VERSION 5.8 ;
BUSBITCHARS "[]" ;
DIVIDERCHAR "/" ;
UNITS
    DATABASE MICRONS 1000 ;
END UNITS

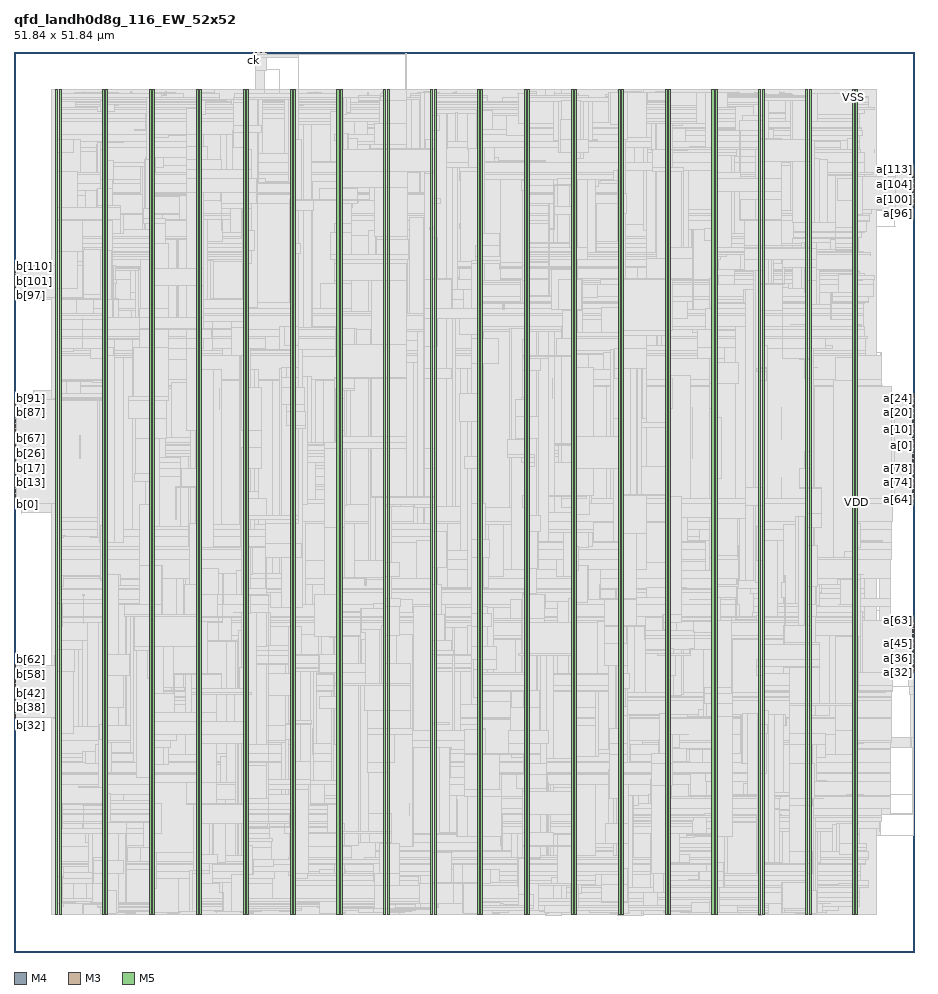
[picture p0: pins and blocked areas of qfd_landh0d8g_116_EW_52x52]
MACRO qfd_landh0d8g_116_EW_52x52
  FOREIGN qfd_landh0d8g_116_EW_52x52 0 0 ;
  CLASS BLOCK ;
  SIZE 51.84 BY 51.84 ;
  PIN a[0]
    DIRECTION INPUT ;
    USE SIGNAL ;
    PORT
      LAYER M4 ;
        RECT  51.756 29.136 51.84 29.16 ;
    END
  END a[0]
  PIN a[100]
    DIRECTION INPUT ;
    USE SIGNAL ;
    PORT
      LAYER M4 ;
        RECT  51.756 43.344 51.84 43.368 ;
    END
  END a[100]
  PIN a[101]
    DIRECTION INPUT ;
    USE SIGNAL ;
    PORT
      LAYER M4 ;
        RECT  51.756 43.44 51.84 43.464 ;
    END
  END a[101]
  PIN a[102]
    DIRECTION INPUT ;
    USE SIGNAL ;
    PORT
      LAYER M4 ;
        RECT  51.756 43.536 51.84 43.56 ;
    END
  END a[102]
  PIN a[103]
    DIRECTION INPUT ;
    USE SIGNAL ;
    PORT
      LAYER M4 ;
        RECT  51.756 43.632 51.84 43.656 ;
    END
  END a[103]
  PIN a[104]
    DIRECTION INPUT ;
    USE SIGNAL ;
    PORT
      LAYER M4 ;
        RECT  51.756 43.728 51.84 43.752 ;
    END
  END a[104]
  PIN a[105]
    DIRECTION INPUT ;
    USE SIGNAL ;
    PORT
      LAYER M4 ;
        RECT  51.756 43.824 51.84 43.848 ;
    END
  END a[105]
  PIN a[106]
    DIRECTION INPUT ;
    USE SIGNAL ;
    PORT
      LAYER M4 ;
        RECT  51.756 43.92 51.84 43.944 ;
    END
  END a[106]
  PIN a[107]
    DIRECTION INPUT ;
    USE SIGNAL ;
    PORT
      LAYER M4 ;
        RECT  51.756 44.016 51.84 44.04 ;
    END
  END a[107]
  PIN a[108]
    DIRECTION INPUT ;
    USE SIGNAL ;
    PORT
      LAYER M4 ;
        RECT  51.756 44.112 51.84 44.136 ;
    END
  END a[108]
  PIN a[109]
    DIRECTION INPUT ;
    USE SIGNAL ;
    PORT
      LAYER M4 ;
        RECT  51.756 44.208 51.84 44.232 ;
    END
  END a[109]
  PIN a[10]
    DIRECTION INPUT ;
    USE SIGNAL ;
    PORT
      LAYER M4 ;
        RECT  51.756 30.096 51.84 30.12 ;
    END
  END a[10]
  PIN a[110]
    DIRECTION INPUT ;
    USE SIGNAL ;
    PORT
      LAYER M4 ;
        RECT  51.756 44.304 51.84 44.328 ;
    END
  END a[110]
  PIN a[111]
    DIRECTION INPUT ;
    USE SIGNAL ;
    PORT
      LAYER M4 ;
        RECT  51.756 44.4 51.84 44.424 ;
    END
  END a[111]
  PIN a[112]
    DIRECTION INPUT ;
    USE SIGNAL ;
    PORT
      LAYER M4 ;
        RECT  51.756 44.496 51.84 44.52 ;
    END
  END a[112]
  PIN a[113]
    DIRECTION INPUT ;
    USE SIGNAL ;
    PORT
      LAYER M4 ;
        RECT  51.756 44.592 51.84 44.616 ;
    END
  END a[113]
  PIN a[114]
    DIRECTION INPUT ;
    USE SIGNAL ;
    PORT
      LAYER M4 ;
        RECT  51.756 44.688 51.84 44.712 ;
    END
  END a[114]
  PIN a[115]
    DIRECTION INPUT ;
    USE SIGNAL ;
    PORT
      LAYER M4 ;
        RECT  51.756 44.784 51.84 44.808 ;
    END
  END a[115]
  PIN a[11]
    DIRECTION INPUT ;
    USE SIGNAL ;
    PORT
      LAYER M4 ;
        RECT  51.756 30.192 51.84 30.216 ;
    END
  END a[11]
  PIN a[12]
    DIRECTION INPUT ;
    USE SIGNAL ;
    PORT
      LAYER M4 ;
        RECT  51.756 30.288 51.84 30.312 ;
    END
  END a[12]
  PIN a[13]
    DIRECTION INPUT ;
    USE SIGNAL ;
    PORT
      LAYER M4 ;
        RECT  51.756 30.384 51.84 30.408 ;
    END
  END a[13]
  PIN a[14]
    DIRECTION INPUT ;
    USE SIGNAL ;
    PORT
      LAYER M4 ;
        RECT  51.756 30.48 51.84 30.504 ;
    END
  END a[14]
  PIN a[15]
    DIRECTION INPUT ;
    USE SIGNAL ;
    PORT
      LAYER M4 ;
        RECT  51.756 30.576 51.84 30.6 ;
    END
  END a[15]
  PIN a[16]
    DIRECTION INPUT ;
    USE SIGNAL ;
    PORT
      LAYER M4 ;
        RECT  51.756 30.672 51.84 30.696 ;
    END
  END a[16]
  PIN a[17]
    DIRECTION INPUT ;
    USE SIGNAL ;
    PORT
      LAYER M4 ;
        RECT  51.756 30.768 51.84 30.792 ;
    END
  END a[17]
  PIN a[18]
    DIRECTION INPUT ;
    USE SIGNAL ;
    PORT
      LAYER M4 ;
        RECT  51.756 30.864 51.84 30.888 ;
    END
  END a[18]
  PIN a[19]
    DIRECTION INPUT ;
    USE SIGNAL ;
    PORT
      LAYER M4 ;
        RECT  51.756 30.96 51.84 30.984 ;
    END
  END a[19]
  PIN a[1]
    DIRECTION INPUT ;
    USE SIGNAL ;
    PORT
      LAYER M4 ;
        RECT  51.756 29.232 51.84 29.256 ;
    END
  END a[1]
  PIN a[20]
    DIRECTION INPUT ;
    USE SIGNAL ;
    PORT
      LAYER M4 ;
        RECT  51.756 31.056 51.84 31.08 ;
    END
  END a[20]
  PIN a[21]
    DIRECTION INPUT ;
    USE SIGNAL ;
    PORT
      LAYER M4 ;
        RECT  51.756 31.152 51.84 31.176 ;
    END
  END a[21]
  PIN a[22]
    DIRECTION INPUT ;
    USE SIGNAL ;
    PORT
      LAYER M4 ;
        RECT  51.756 31.248 51.84 31.272 ;
    END
  END a[22]
  PIN a[23]
    DIRECTION INPUT ;
    USE SIGNAL ;
    PORT
      LAYER M4 ;
        RECT  51.756 31.344 51.84 31.368 ;
    END
  END a[23]
  PIN a[24]
    DIRECTION INPUT ;
    USE SIGNAL ;
    PORT
      LAYER M4 ;
        RECT  51.756 31.44 51.84 31.464 ;
    END
  END a[24]
  PIN a[25]
    DIRECTION INPUT ;
    USE SIGNAL ;
    PORT
      LAYER M4 ;
        RECT  51.756 31.536 51.84 31.56 ;
    END
  END a[25]
  PIN a[26]
    DIRECTION INPUT ;
    USE SIGNAL ;
    PORT
      LAYER M4 ;
        RECT  51.756 31.632 51.84 31.656 ;
    END
  END a[26]
  PIN a[27]
    DIRECTION INPUT ;
    USE SIGNAL ;
    PORT
      LAYER M4 ;
        RECT  51.756 31.728 51.84 31.752 ;
    END
  END a[27]
  PIN a[28]
    DIRECTION INPUT ;
    USE SIGNAL ;
    PORT
      LAYER M4 ;
        RECT  51.756 31.824 51.84 31.848 ;
    END
  END a[28]
  PIN a[29]
    DIRECTION INPUT ;
    USE SIGNAL ;
    PORT
      LAYER M4 ;
        RECT  51.756 31.92 51.84 31.944 ;
    END
  END a[29]
  PIN a[2]
    DIRECTION INPUT ;
    USE SIGNAL ;
    PORT
      LAYER M4 ;
        RECT  51.756 29.328 51.84 29.352 ;
    END
  END a[2]
  PIN a[30]
    DIRECTION INPUT ;
    USE SIGNAL ;
    PORT
      LAYER M4 ;
        RECT  51.756 32.016 51.84 32.04 ;
    END
  END a[30]
  PIN a[31]
    DIRECTION INPUT ;
    USE SIGNAL ;
    PORT
      LAYER M4 ;
        RECT  51.756 32.112 51.84 32.136 ;
    END
  END a[31]
  PIN a[32]
    DIRECTION INPUT ;
    USE SIGNAL ;
    PORT
      LAYER M4 ;
        RECT  51.756 16.08 51.84 16.104 ;
    END
  END a[32]
  PIN a[33]
    DIRECTION INPUT ;
    USE SIGNAL ;
    PORT
      LAYER M4 ;
        RECT  51.756 16.176 51.84 16.2 ;
    END
  END a[33]
  PIN a[34]
    DIRECTION INPUT ;
    USE SIGNAL ;
    PORT
      LAYER M4 ;
        RECT  51.756 16.272 51.84 16.296 ;
    END
  END a[34]
  PIN a[35]
    DIRECTION INPUT ;
    USE SIGNAL ;
    PORT
      LAYER M4 ;
        RECT  51.756 16.368 51.84 16.392 ;
    END
  END a[35]
  PIN a[36]
    DIRECTION INPUT ;
    USE SIGNAL ;
    PORT
      LAYER M4 ;
        RECT  51.756 16.464 51.84 16.488 ;
    END
  END a[36]
  PIN a[37]
    DIRECTION INPUT ;
    USE SIGNAL ;
    PORT
      LAYER M4 ;
        RECT  51.756 16.56 51.84 16.584 ;
    END
  END a[37]
  PIN a[38]
    DIRECTION INPUT ;
    USE SIGNAL ;
    PORT
      LAYER M4 ;
        RECT  51.756 16.656 51.84 16.68 ;
    END
  END a[38]
  PIN a[39]
    DIRECTION INPUT ;
    USE SIGNAL ;
    PORT
      LAYER M4 ;
        RECT  51.756 16.752 51.84 16.776 ;
    END
  END a[39]
  PIN a[3]
    DIRECTION INPUT ;
    USE SIGNAL ;
    PORT
      LAYER M4 ;
        RECT  51.756 29.424 51.84 29.448 ;
    END
  END a[3]
  PIN a[40]
    DIRECTION INPUT ;
    USE SIGNAL ;
    PORT
      LAYER M4 ;
        RECT  51.756 16.848 51.84 16.872 ;
    END
  END a[40]
  PIN a[41]
    DIRECTION INPUT ;
    USE SIGNAL ;
    PORT
      LAYER M4 ;
        RECT  51.756 16.944 51.84 16.968 ;
    END
  END a[41]
  PIN a[42]
    DIRECTION INPUT ;
    USE SIGNAL ;
    PORT
      LAYER M4 ;
        RECT  51.756 17.04 51.84 17.064 ;
    END
  END a[42]
  PIN a[43]
    DIRECTION INPUT ;
    USE SIGNAL ;
    PORT
      LAYER M4 ;
        RECT  51.756 17.136 51.84 17.16 ;
    END
  END a[43]
  PIN a[44]
    DIRECTION INPUT ;
    USE SIGNAL ;
    PORT
      LAYER M4 ;
        RECT  51.756 17.232 51.84 17.256 ;
    END
  END a[44]
  PIN a[45]
    DIRECTION INPUT ;
    USE SIGNAL ;
    PORT
      LAYER M4 ;
        RECT  51.756 17.328 51.84 17.352 ;
    END
  END a[45]
  PIN a[46]
    DIRECTION INPUT ;
    USE SIGNAL ;
    PORT
      LAYER M4 ;
        RECT  51.756 17.424 51.84 17.448 ;
    END
  END a[46]
  PIN a[47]
    DIRECTION INPUT ;
    USE SIGNAL ;
    PORT
      LAYER M4 ;
        RECT  51.756 17.52 51.84 17.544 ;
    END
  END a[47]
  PIN a[48]
    DIRECTION INPUT ;
    USE SIGNAL ;
    PORT
      LAYER M4 ;
        RECT  51.756 17.616 51.84 17.64 ;
    END
  END a[48]
  PIN a[49]
    DIRECTION INPUT ;
    USE SIGNAL ;
    PORT
      LAYER M4 ;
        RECT  51.756 17.712 51.84 17.736 ;
    END
  END a[49]
  PIN a[4]
    DIRECTION INPUT ;
    USE SIGNAL ;
    PORT
      LAYER M4 ;
        RECT  51.756 29.52 51.84 29.544 ;
    END
  END a[4]
  PIN a[50]
    DIRECTION INPUT ;
    USE SIGNAL ;
    PORT
      LAYER M4 ;
        RECT  51.756 17.808 51.84 17.832 ;
    END
  END a[50]
  PIN a[51]
    DIRECTION INPUT ;
    USE SIGNAL ;
    PORT
      LAYER M4 ;
        RECT  51.756 17.904 51.84 17.928 ;
    END
  END a[51]
  PIN a[52]
    DIRECTION INPUT ;
    USE SIGNAL ;
    PORT
      LAYER M4 ;
        RECT  51.756 18 51.84 18.024 ;
    END
  END a[52]
  PIN a[53]
    DIRECTION INPUT ;
    USE SIGNAL ;
    PORT
      LAYER M4 ;
        RECT  51.756 18.096 51.84 18.12 ;
    END
  END a[53]
  PIN a[54]
    DIRECTION INPUT ;
    USE SIGNAL ;
    PORT
      LAYER M4 ;
        RECT  51.756 18.192 51.84 18.216 ;
    END
  END a[54]
  PIN a[55]
    DIRECTION INPUT ;
    USE SIGNAL ;
    PORT
      LAYER M4 ;
        RECT  51.756 18.288 51.84 18.312 ;
    END
  END a[55]
  PIN a[56]
    DIRECTION INPUT ;
    USE SIGNAL ;
    PORT
      LAYER M4 ;
        RECT  51.756 18.384 51.84 18.408 ;
    END
  END a[56]
  PIN a[57]
    DIRECTION INPUT ;
    USE SIGNAL ;
    PORT
      LAYER M4 ;
        RECT  51.756 18.48 51.84 18.504 ;
    END
  END a[57]
  PIN a[58]
    DIRECTION INPUT ;
    USE SIGNAL ;
    PORT
      LAYER M4 ;
        RECT  51.756 18.576 51.84 18.6 ;
    END
  END a[58]
  PIN a[59]
    DIRECTION INPUT ;
    USE SIGNAL ;
    PORT
      LAYER M4 ;
        RECT  51.756 18.672 51.84 18.696 ;
    END
  END a[59]
  PIN a[5]
    DIRECTION INPUT ;
    USE SIGNAL ;
    PORT
      LAYER M4 ;
        RECT  51.756 29.616 51.84 29.64 ;
    END
  END a[5]
  PIN a[60]
    DIRECTION INPUT ;
    USE SIGNAL ;
    PORT
      LAYER M4 ;
        RECT  51.756 18.768 51.84 18.792 ;
    END
  END a[60]
  PIN a[61]
    DIRECTION INPUT ;
    USE SIGNAL ;
    PORT
      LAYER M4 ;
        RECT  51.756 18.864 51.84 18.888 ;
    END
  END a[61]
  PIN a[62]
    DIRECTION INPUT ;
    USE SIGNAL ;
    PORT
      LAYER M4 ;
        RECT  51.756 18.96 51.84 18.984 ;
    END
  END a[62]
  PIN a[63]
    DIRECTION INPUT ;
    USE SIGNAL ;
    PORT
      LAYER M4 ;
        RECT  51.756 19.056 51.84 19.08 ;
    END
  END a[63]
  PIN a[64]
    DIRECTION INPUT ;
    USE SIGNAL ;
    PORT
      LAYER M4 ;
        RECT  51.756 26.064 51.84 26.088 ;
    END
  END a[64]
  PIN a[65]
    DIRECTION INPUT ;
    USE SIGNAL ;
    PORT
      LAYER M4 ;
        RECT  51.756 26.16 51.84 26.184 ;
    END
  END a[65]
  PIN a[66]
    DIRECTION INPUT ;
    USE SIGNAL ;
    PORT
      LAYER M4 ;
        RECT  51.756 26.256 51.84 26.28 ;
    END
  END a[66]
  PIN a[67]
    DIRECTION INPUT ;
    USE SIGNAL ;
    PORT
      LAYER M4 ;
        RECT  51.756 26.352 51.84 26.376 ;
    END
  END a[67]
  PIN a[68]
    DIRECTION INPUT ;
    USE SIGNAL ;
    PORT
      LAYER M4 ;
        RECT  51.756 26.448 51.84 26.472 ;
    END
  END a[68]
  PIN a[69]
    DIRECTION INPUT ;
    USE SIGNAL ;
    PORT
      LAYER M4 ;
        RECT  51.756 26.544 51.84 26.568 ;
    END
  END a[69]
  PIN a[6]
    DIRECTION INPUT ;
    USE SIGNAL ;
    PORT
      LAYER M4 ;
        RECT  51.756 29.712 51.84 29.736 ;
    END
  END a[6]
  PIN a[70]
    DIRECTION INPUT ;
    USE SIGNAL ;
    PORT
      LAYER M4 ;
        RECT  51.756 26.64 51.84 26.664 ;
    END
  END a[70]
  PIN a[71]
    DIRECTION INPUT ;
    USE SIGNAL ;
    PORT
      LAYER M4 ;
        RECT  51.756 26.736 51.84 26.76 ;
    END
  END a[71]
  PIN a[72]
    DIRECTION INPUT ;
    USE SIGNAL ;
    PORT
      LAYER M4 ;
        RECT  51.756 26.832 51.84 26.856 ;
    END
  END a[72]
  PIN a[73]
    DIRECTION INPUT ;
    USE SIGNAL ;
    PORT
      LAYER M4 ;
        RECT  51.756 26.928 51.84 26.952 ;
    END
  END a[73]
  PIN a[74]
    DIRECTION INPUT ;
    USE SIGNAL ;
    PORT
      LAYER M4 ;
        RECT  51.756 27.024 51.84 27.048 ;
    END
  END a[74]
  PIN a[75]
    DIRECTION INPUT ;
    USE SIGNAL ;
    PORT
      LAYER M4 ;
        RECT  51.756 27.12 51.84 27.144 ;
    END
  END a[75]
  PIN a[76]
    DIRECTION INPUT ;
    USE SIGNAL ;
    PORT
      LAYER M4 ;
        RECT  51.756 27.216 51.84 27.24 ;
    END
  END a[76]
  PIN a[77]
    DIRECTION INPUT ;
    USE SIGNAL ;
    PORT
      LAYER M4 ;
        RECT  51.756 27.312 51.84 27.336 ;
    END
  END a[77]
  PIN a[78]
    DIRECTION INPUT ;
    USE SIGNAL ;
    PORT
      LAYER M4 ;
        RECT  51.756 27.408 51.84 27.432 ;
    END
  END a[78]
  PIN a[79]
    DIRECTION INPUT ;
    USE SIGNAL ;
    PORT
      LAYER M4 ;
        RECT  51.756 27.504 51.84 27.528 ;
    END
  END a[79]
  PIN a[7]
    DIRECTION INPUT ;
    USE SIGNAL ;
    PORT
      LAYER M4 ;
        RECT  51.756 29.808 51.84 29.832 ;
    END
  END a[7]
  PIN a[80]
    DIRECTION INPUT ;
    USE SIGNAL ;
    PORT
      LAYER M4 ;
        RECT  51.756 27.6 51.84 27.624 ;
    END
  END a[80]
  PIN a[81]
    DIRECTION INPUT ;
    USE SIGNAL ;
    PORT
      LAYER M4 ;
        RECT  51.756 27.696 51.84 27.72 ;
    END
  END a[81]
  PIN a[82]
    DIRECTION INPUT ;
    USE SIGNAL ;
    PORT
      LAYER M4 ;
        RECT  51.756 27.792 51.84 27.816 ;
    END
  END a[82]
  PIN a[83]
    DIRECTION INPUT ;
    USE SIGNAL ;
    PORT
      LAYER M4 ;
        RECT  51.756 27.888 51.84 27.912 ;
    END
  END a[83]
  PIN a[84]
    DIRECTION INPUT ;
    USE SIGNAL ;
    PORT
      LAYER M4 ;
        RECT  51.756 27.984 51.84 28.008 ;
    END
  END a[84]
  PIN a[85]
    DIRECTION INPUT ;
    USE SIGNAL ;
    PORT
      LAYER M4 ;
        RECT  51.756 28.08 51.84 28.104 ;
    END
  END a[85]
  PIN a[86]
    DIRECTION INPUT ;
    USE SIGNAL ;
    PORT
      LAYER M4 ;
        RECT  51.756 28.176 51.84 28.2 ;
    END
  END a[86]
  PIN a[87]
    DIRECTION INPUT ;
    USE SIGNAL ;
    PORT
      LAYER M4 ;
        RECT  51.756 28.272 51.84 28.296 ;
    END
  END a[87]
  PIN a[88]
    DIRECTION INPUT ;
    USE SIGNAL ;
    PORT
      LAYER M4 ;
        RECT  51.756 28.368 51.84 28.392 ;
    END
  END a[88]
  PIN a[89]
    DIRECTION INPUT ;
    USE SIGNAL ;
    PORT
      LAYER M4 ;
        RECT  51.756 28.464 51.84 28.488 ;
    END
  END a[89]
  PIN a[8]
    DIRECTION INPUT ;
    USE SIGNAL ;
    PORT
      LAYER M4 ;
        RECT  51.756 29.904 51.84 29.928 ;
    END
  END a[8]
  PIN a[90]
    DIRECTION INPUT ;
    USE SIGNAL ;
    PORT
      LAYER M4 ;
        RECT  51.756 28.56 51.84 28.584 ;
    END
  END a[90]
  PIN a[91]
    DIRECTION INPUT ;
    USE SIGNAL ;
    PORT
      LAYER M4 ;
        RECT  51.756 28.656 51.84 28.68 ;
    END
  END a[91]
  PIN a[92]
    DIRECTION INPUT ;
    USE SIGNAL ;
    PORT
      LAYER M4 ;
        RECT  51.756 28.752 51.84 28.776 ;
    END
  END a[92]
  PIN a[93]
    DIRECTION INPUT ;
    USE SIGNAL ;
    PORT
      LAYER M4 ;
        RECT  51.756 28.848 51.84 28.872 ;
    END
  END a[93]
  PIN a[94]
    DIRECTION INPUT ;
    USE SIGNAL ;
    PORT
      LAYER M4 ;
        RECT  51.756 28.944 51.84 28.968 ;
    END
  END a[94]
  PIN a[95]
    DIRECTION INPUT ;
    USE SIGNAL ;
    PORT
      LAYER M4 ;
        RECT  51.756 29.04 51.84 29.064 ;
    END
  END a[95]
  PIN a[96]
    DIRECTION INPUT ;
    USE SIGNAL ;
    PORT
      LAYER M4 ;
        RECT  51.756 42.96 51.84 42.984 ;
    END
  END a[96]
  PIN a[97]
    DIRECTION INPUT ;
    USE SIGNAL ;
    PORT
      LAYER M4 ;
        RECT  51.756 43.056 51.84 43.08 ;
    END
  END a[97]
  PIN a[98]
    DIRECTION INPUT ;
    USE SIGNAL ;
    PORT
      LAYER M4 ;
        RECT  51.756 43.152 51.84 43.176 ;
    END
  END a[98]
  PIN a[99]
    DIRECTION INPUT ;
    USE SIGNAL ;
    PORT
      LAYER M4 ;
        RECT  51.756 43.248 51.84 43.272 ;
    END
  END a[99]
  PIN a[9]
    DIRECTION INPUT ;
    USE SIGNAL ;
    PORT
      LAYER M4 ;
        RECT  51.756 30 51.84 30.024 ;
    END
  END a[9]
  PIN b[0]
    DIRECTION OUTPUT ;
    USE SIGNAL ;
    PORT
      LAYER M4 ;
        RECT  0 25.776 0.084 25.8 ;
    END
  END b[0]
  PIN b[100]
    DIRECTION OUTPUT ;
    USE SIGNAL ;
    PORT
      LAYER M4 ;
        RECT  0 38.064 0.084 38.088 ;
    END
  END b[100]
  PIN b[101]
    DIRECTION OUTPUT ;
    USE SIGNAL ;
    PORT
      LAYER M4 ;
        RECT  0 38.16 0.084 38.184 ;
    END
  END b[101]
  PIN b[102]
    DIRECTION OUTPUT ;
    USE SIGNAL ;
    PORT
      LAYER M4 ;
        RECT  0 38.256 0.084 38.28 ;
    END
  END b[102]
  PIN b[103]
    DIRECTION OUTPUT ;
    USE SIGNAL ;
    PORT
      LAYER M4 ;
        RECT  0 38.352 0.084 38.376 ;
    END
  END b[103]
  PIN b[104]
    DIRECTION OUTPUT ;
    USE SIGNAL ;
    PORT
      LAYER M4 ;
        RECT  0 38.448 0.084 38.472 ;
    END
  END b[104]
  PIN b[105]
    DIRECTION OUTPUT ;
    USE SIGNAL ;
    PORT
      LAYER M4 ;
        RECT  0 38.544 0.084 38.568 ;
    END
  END b[105]
  PIN b[106]
    DIRECTION OUTPUT ;
    USE SIGNAL ;
    PORT
      LAYER M4 ;
        RECT  0 38.64 0.084 38.664 ;
    END
  END b[106]
  PIN b[107]
    DIRECTION OUTPUT ;
    USE SIGNAL ;
    PORT
      LAYER M4 ;
        RECT  0 38.736 0.084 38.76 ;
    END
  END b[107]
  PIN b[108]
    DIRECTION OUTPUT ;
    USE SIGNAL ;
    PORT
      LAYER M4 ;
        RECT  0 38.832 0.084 38.856 ;
    END
  END b[108]
  PIN b[109]
    DIRECTION OUTPUT ;
    USE SIGNAL ;
    PORT
      LAYER M4 ;
        RECT  0 38.928 0.084 38.952 ;
    END
  END b[109]
  PIN b[10]
    DIRECTION OUTPUT ;
    USE SIGNAL ;
    PORT
      LAYER M4 ;
        RECT  0 26.736 0.084 26.76 ;
    END
  END b[10]
  PIN b[110]
    DIRECTION OUTPUT ;
    USE SIGNAL ;
    PORT
      LAYER M4 ;
        RECT  0 39.024 0.084 39.048 ;
    END
  END b[110]
  PIN b[111]
    DIRECTION OUTPUT ;
    USE SIGNAL ;
    PORT
      LAYER M4 ;
        RECT  0 39.12 0.084 39.144 ;
    END
  END b[111]
  PIN b[112]
    DIRECTION OUTPUT ;
    USE SIGNAL ;
    PORT
      LAYER M4 ;
        RECT  0 39.216 0.084 39.24 ;
    END
  END b[112]
  PIN b[113]
    DIRECTION OUTPUT ;
    USE SIGNAL ;
    PORT
      LAYER M4 ;
        RECT  0 39.312 0.084 39.336 ;
    END
  END b[113]
  PIN b[114]
    DIRECTION OUTPUT ;
    USE SIGNAL ;
    PORT
      LAYER M4 ;
        RECT  0 39.408 0.084 39.432 ;
    END
  END b[114]
  PIN b[115]
    DIRECTION OUTPUT ;
    USE SIGNAL ;
    PORT
      LAYER M4 ;
        RECT  0 39.504 0.084 39.528 ;
    END
  END b[115]
  PIN b[11]
    DIRECTION OUTPUT ;
    USE SIGNAL ;
    PORT
      LAYER M4 ;
        RECT  0 26.832 0.084 26.856 ;
    END
  END b[11]
  PIN b[12]
    DIRECTION OUTPUT ;
    USE SIGNAL ;
    PORT
      LAYER M4 ;
        RECT  0 26.928 0.084 26.952 ;
    END
  END b[12]
  PIN b[13]
    DIRECTION OUTPUT ;
    USE SIGNAL ;
    PORT
      LAYER M4 ;
        RECT  0 27.024 0.084 27.048 ;
    END
  END b[13]
  PIN b[14]
    DIRECTION OUTPUT ;
    USE SIGNAL ;
    PORT
      LAYER M4 ;
        RECT  0 27.12 0.084 27.144 ;
    END
  END b[14]
  PIN b[15]
    DIRECTION OUTPUT ;
    USE SIGNAL ;
    PORT
      LAYER M4 ;
        RECT  0 27.216 0.084 27.24 ;
    END
  END b[15]
  PIN b[16]
    DIRECTION OUTPUT ;
    USE SIGNAL ;
    PORT
      LAYER M4 ;
        RECT  0 27.312 0.084 27.336 ;
    END
  END b[16]
  PIN b[17]
    DIRECTION OUTPUT ;
    USE SIGNAL ;
    PORT
      LAYER M4 ;
        RECT  0 27.408 0.084 27.432 ;
    END
  END b[17]
  PIN b[18]
    DIRECTION OUTPUT ;
    USE SIGNAL ;
    PORT
      LAYER M4 ;
        RECT  0 27.504 0.084 27.528 ;
    END
  END b[18]
  PIN b[19]
    DIRECTION OUTPUT ;
    USE SIGNAL ;
    PORT
      LAYER M4 ;
        RECT  0 27.6 0.084 27.624 ;
    END
  END b[19]
  PIN b[1]
    DIRECTION OUTPUT ;
    USE SIGNAL ;
    PORT
      LAYER M4 ;
        RECT  0 25.872 0.084 25.896 ;
    END
  END b[1]
  PIN b[20]
    DIRECTION OUTPUT ;
    USE SIGNAL ;
    PORT
      LAYER M4 ;
        RECT  0 27.696 0.084 27.72 ;
    END
  END b[20]
  PIN b[21]
    DIRECTION OUTPUT ;
    USE SIGNAL ;
    PORT
      LAYER M4 ;
        RECT  0 27.792 0.084 27.816 ;
    END
  END b[21]
  PIN b[22]
    DIRECTION OUTPUT ;
    USE SIGNAL ;
    PORT
      LAYER M4 ;
        RECT  0 27.888 0.084 27.912 ;
    END
  END b[22]
  PIN b[23]
    DIRECTION OUTPUT ;
    USE SIGNAL ;
    PORT
      LAYER M4 ;
        RECT  0 27.984 0.084 28.008 ;
    END
  END b[23]
  PIN b[24]
    DIRECTION OUTPUT ;
    USE SIGNAL ;
    PORT
      LAYER M4 ;
        RECT  0 28.08 0.084 28.104 ;
    END
  END b[24]
  PIN b[25]
    DIRECTION OUTPUT ;
    USE SIGNAL ;
    PORT
      LAYER M4 ;
        RECT  0 28.176 0.084 28.2 ;
    END
  END b[25]
  PIN b[26]
    DIRECTION OUTPUT ;
    USE SIGNAL ;
    PORT
      LAYER M4 ;
        RECT  0 28.272 0.084 28.296 ;
    END
  END b[26]
  PIN b[27]
    DIRECTION OUTPUT ;
    USE SIGNAL ;
    PORT
      LAYER M4 ;
        RECT  0 28.368 0.084 28.392 ;
    END
  END b[27]
  PIN b[28]
    DIRECTION OUTPUT ;
    USE SIGNAL ;
    PORT
      LAYER M4 ;
        RECT  0 28.464 0.084 28.488 ;
    END
  END b[28]
  PIN b[29]
    DIRECTION OUTPUT ;
    USE SIGNAL ;
    PORT
      LAYER M4 ;
        RECT  0 28.56 0.084 28.584 ;
    END
  END b[29]
  PIN b[2]
    DIRECTION OUTPUT ;
    USE SIGNAL ;
    PORT
      LAYER M4 ;
        RECT  0 25.968 0.084 25.992 ;
    END
  END b[2]
  PIN b[30]
    DIRECTION OUTPUT ;
    USE SIGNAL ;
    PORT
      LAYER M4 ;
        RECT  0 28.656 0.084 28.68 ;
    END
  END b[30]
  PIN b[31]
    DIRECTION OUTPUT ;
    USE SIGNAL ;
    PORT
      LAYER M4 ;
        RECT  0 28.752 0.084 28.776 ;
    END
  END b[31]
  PIN b[32]
    DIRECTION OUTPUT ;
    USE SIGNAL ;
    PORT
      LAYER M4 ;
        RECT  0 13.488 0.084 13.512 ;
    END
  END b[32]
  PIN b[33]
    DIRECTION OUTPUT ;
    USE SIGNAL ;
    PORT
      LAYER M4 ;
        RECT  0 13.584 0.084 13.608 ;
    END
  END b[33]
  PIN b[34]
    DIRECTION OUTPUT ;
    USE SIGNAL ;
    PORT
      LAYER M4 ;
        RECT  0 13.68 0.084 13.704 ;
    END
  END b[34]
  PIN b[35]
    DIRECTION OUTPUT ;
    USE SIGNAL ;
    PORT
      LAYER M4 ;
        RECT  0 13.776 0.084 13.8 ;
    END
  END b[35]
  PIN b[36]
    DIRECTION OUTPUT ;
    USE SIGNAL ;
    PORT
      LAYER M4 ;
        RECT  0 13.872 0.084 13.896 ;
    END
  END b[36]
  PIN b[37]
    DIRECTION OUTPUT ;
    USE SIGNAL ;
    PORT
      LAYER M4 ;
        RECT  0 13.968 0.084 13.992 ;
    END
  END b[37]
  PIN b[38]
    DIRECTION OUTPUT ;
    USE SIGNAL ;
    PORT
      LAYER M4 ;
        RECT  0 14.064 0.084 14.088 ;
    END
  END b[38]
  PIN b[39]
    DIRECTION OUTPUT ;
    USE SIGNAL ;
    PORT
      LAYER M4 ;
        RECT  0 14.16 0.084 14.184 ;
    END
  END b[39]
  PIN b[3]
    DIRECTION OUTPUT ;
    USE SIGNAL ;
    PORT
      LAYER M4 ;
        RECT  0 26.064 0.084 26.088 ;
    END
  END b[3]
  PIN b[40]
    DIRECTION OUTPUT ;
    USE SIGNAL ;
    PORT
      LAYER M4 ;
        RECT  0 14.256 0.084 14.28 ;
    END
  END b[40]
  PIN b[41]
    DIRECTION OUTPUT ;
    USE SIGNAL ;
    PORT
      LAYER M4 ;
        RECT  0 14.352 0.084 14.376 ;
    END
  END b[41]
  PIN b[42]
    DIRECTION OUTPUT ;
    USE SIGNAL ;
    PORT
      LAYER M4 ;
        RECT  0 14.448 0.084 14.472 ;
    END
  END b[42]
  PIN b[43]
    DIRECTION OUTPUT ;
    USE SIGNAL ;
    PORT
      LAYER M4 ;
        RECT  0 14.544 0.084 14.568 ;
    END
  END b[43]
  PIN b[44]
    DIRECTION OUTPUT ;
    USE SIGNAL ;
    PORT
      LAYER M4 ;
        RECT  0 14.64 0.084 14.664 ;
    END
  END b[44]
  PIN b[45]
    DIRECTION OUTPUT ;
    USE SIGNAL ;
    PORT
      LAYER M4 ;
        RECT  0 14.736 0.084 14.76 ;
    END
  END b[45]
  PIN b[46]
    DIRECTION OUTPUT ;
    USE SIGNAL ;
    PORT
      LAYER M4 ;
        RECT  0 14.832 0.084 14.856 ;
    END
  END b[46]
  PIN b[47]
    DIRECTION OUTPUT ;
    USE SIGNAL ;
    PORT
      LAYER M4 ;
        RECT  0 14.928 0.084 14.952 ;
    END
  END b[47]
  PIN b[48]
    DIRECTION OUTPUT ;
    USE SIGNAL ;
    PORT
      LAYER M4 ;
        RECT  0 15.024 0.084 15.048 ;
    END
  END b[48]
  PIN b[49]
    DIRECTION OUTPUT ;
    USE SIGNAL ;
    PORT
      LAYER M4 ;
        RECT  0 15.12 0.084 15.144 ;
    END
  END b[49]
  PIN b[4]
    DIRECTION OUTPUT ;
    USE SIGNAL ;
    PORT
      LAYER M4 ;
        RECT  0 26.16 0.084 26.184 ;
    END
  END b[4]
  PIN b[50]
    DIRECTION OUTPUT ;
    USE SIGNAL ;
    PORT
      LAYER M4 ;
        RECT  0 15.216 0.084 15.24 ;
    END
  END b[50]
  PIN b[51]
    DIRECTION OUTPUT ;
    USE SIGNAL ;
    PORT
      LAYER M4 ;
        RECT  0 15.312 0.084 15.336 ;
    END
  END b[51]
  PIN b[52]
    DIRECTION OUTPUT ;
    USE SIGNAL ;
    PORT
      LAYER M4 ;
        RECT  0 15.408 0.084 15.432 ;
    END
  END b[52]
  PIN b[53]
    DIRECTION OUTPUT ;
    USE SIGNAL ;
    PORT
      LAYER M4 ;
        RECT  0 15.504 0.084 15.528 ;
    END
  END b[53]
  PIN b[54]
    DIRECTION OUTPUT ;
    USE SIGNAL ;
    PORT
      LAYER M4 ;
        RECT  0 15.6 0.084 15.624 ;
    END
  END b[54]
  PIN b[55]
    DIRECTION OUTPUT ;
    USE SIGNAL ;
    PORT
      LAYER M4 ;
        RECT  0 15.696 0.084 15.72 ;
    END
  END b[55]
  PIN b[56]
    DIRECTION OUTPUT ;
    USE SIGNAL ;
    PORT
      LAYER M4 ;
        RECT  0 15.792 0.084 15.816 ;
    END
  END b[56]
  PIN b[57]
    DIRECTION OUTPUT ;
    USE SIGNAL ;
    PORT
      LAYER M4 ;
        RECT  0 15.888 0.084 15.912 ;
    END
  END b[57]
  PIN b[58]
    DIRECTION OUTPUT ;
    USE SIGNAL ;
    PORT
      LAYER M4 ;
        RECT  0 15.984 0.084 16.008 ;
    END
  END b[58]
  PIN b[59]
    DIRECTION OUTPUT ;
    USE SIGNAL ;
    PORT
      LAYER M4 ;
        RECT  0 16.08 0.084 16.104 ;
    END
  END b[59]
  PIN b[5]
    DIRECTION OUTPUT ;
    USE SIGNAL ;
    PORT
      LAYER M4 ;
        RECT  0 26.256 0.084 26.28 ;
    END
  END b[5]
  PIN b[60]
    DIRECTION OUTPUT ;
    USE SIGNAL ;
    PORT
      LAYER M4 ;
        RECT  0 16.176 0.084 16.2 ;
    END
  END b[60]
  PIN b[61]
    DIRECTION OUTPUT ;
    USE SIGNAL ;
    PORT
      LAYER M4 ;
        RECT  0 16.272 0.084 16.296 ;
    END
  END b[61]
  PIN b[62]
    DIRECTION OUTPUT ;
    USE SIGNAL ;
    PORT
      LAYER M4 ;
        RECT  0 16.368 0.084 16.392 ;
    END
  END b[62]
  PIN b[63]
    DIRECTION OUTPUT ;
    USE SIGNAL ;
    PORT
      LAYER M4 ;
        RECT  0 16.464 0.084 16.488 ;
    END
  END b[63]
  PIN b[64]
    DIRECTION OUTPUT ;
    USE SIGNAL ;
    PORT
      LAYER M4 ;
        RECT  0 28.848 0.084 28.872 ;
    END
  END b[64]
  PIN b[65]
    DIRECTION OUTPUT ;
    USE SIGNAL ;
    PORT
      LAYER M4 ;
        RECT  0 28.944 0.084 28.968 ;
    END
  END b[65]
  PIN b[66]
    DIRECTION OUTPUT ;
    USE SIGNAL ;
    PORT
      LAYER M4 ;
        RECT  0 29.04 0.084 29.064 ;
    END
  END b[66]
  PIN b[67]
    DIRECTION OUTPUT ;
    USE SIGNAL ;
    PORT
      LAYER M4 ;
        RECT  0 29.136 0.084 29.16 ;
    END
  END b[67]
  PIN b[68]
    DIRECTION OUTPUT ;
    USE SIGNAL ;
    PORT
      LAYER M4 ;
        RECT  0 29.232 0.084 29.256 ;
    END
  END b[68]
  PIN b[69]
    DIRECTION OUTPUT ;
    USE SIGNAL ;
    PORT
      LAYER M4 ;
        RECT  0 29.328 0.084 29.352 ;
    END
  END b[69]
  PIN b[6]
    DIRECTION OUTPUT ;
    USE SIGNAL ;
    PORT
      LAYER M4 ;
        RECT  0 26.352 0.084 26.376 ;
    END
  END b[6]
  PIN b[70]
    DIRECTION OUTPUT ;
    USE SIGNAL ;
    PORT
      LAYER M4 ;
        RECT  0 29.424 0.084 29.448 ;
    END
  END b[70]
  PIN b[71]
    DIRECTION OUTPUT ;
    USE SIGNAL ;
    PORT
      LAYER M4 ;
        RECT  0 29.52 0.084 29.544 ;
    END
  END b[71]
  PIN b[72]
    DIRECTION OUTPUT ;
    USE SIGNAL ;
    PORT
      LAYER M4 ;
        RECT  0 29.616 0.084 29.64 ;
    END
  END b[72]
  PIN b[73]
    DIRECTION OUTPUT ;
    USE SIGNAL ;
    PORT
      LAYER M4 ;
        RECT  0 29.712 0.084 29.736 ;
    END
  END b[73]
  PIN b[74]
    DIRECTION OUTPUT ;
    USE SIGNAL ;
    PORT
      LAYER M4 ;
        RECT  0 29.808 0.084 29.832 ;
    END
  END b[74]
  PIN b[75]
    DIRECTION OUTPUT ;
    USE SIGNAL ;
    PORT
      LAYER M4 ;
        RECT  0 29.904 0.084 29.928 ;
    END
  END b[75]
  PIN b[76]
    DIRECTION OUTPUT ;
    USE SIGNAL ;
    PORT
      LAYER M4 ;
        RECT  0 30 0.084 30.024 ;
    END
  END b[76]
  PIN b[77]
    DIRECTION OUTPUT ;
    USE SIGNAL ;
    PORT
      LAYER M4 ;
        RECT  0 30.096 0.084 30.12 ;
    END
  END b[77]
  PIN b[78]
    DIRECTION OUTPUT ;
    USE SIGNAL ;
    PORT
      LAYER M4 ;
        RECT  0 30.192 0.084 30.216 ;
    END
  END b[78]
  PIN b[79]
    DIRECTION OUTPUT ;
    USE SIGNAL ;
    PORT
      LAYER M4 ;
        RECT  0 30.288 0.084 30.312 ;
    END
  END b[79]
  PIN b[7]
    DIRECTION OUTPUT ;
    USE SIGNAL ;
    PORT
      LAYER M4 ;
        RECT  0 26.448 0.084 26.472 ;
    END
  END b[7]
  PIN b[80]
    DIRECTION OUTPUT ;
    USE SIGNAL ;
    PORT
      LAYER M4 ;
        RECT  0 30.384 0.084 30.408 ;
    END
  END b[80]
  PIN b[81]
    DIRECTION OUTPUT ;
    USE SIGNAL ;
    PORT
      LAYER M4 ;
        RECT  0 30.48 0.084 30.504 ;
    END
  END b[81]
  PIN b[82]
    DIRECTION OUTPUT ;
    USE SIGNAL ;
    PORT
      LAYER M4 ;
        RECT  0 30.576 0.084 30.6 ;
    END
  END b[82]
  PIN b[83]
    DIRECTION OUTPUT ;
    USE SIGNAL ;
    PORT
      LAYER M4 ;
        RECT  0 30.672 0.084 30.696 ;
    END
  END b[83]
  PIN b[84]
    DIRECTION OUTPUT ;
    USE SIGNAL ;
    PORT
      LAYER M4 ;
        RECT  0 30.768 0.084 30.792 ;
    END
  END b[84]
  PIN b[85]
    DIRECTION OUTPUT ;
    USE SIGNAL ;
    PORT
      LAYER M4 ;
        RECT  0 30.864 0.084 30.888 ;
    END
  END b[85]
  PIN b[86]
    DIRECTION OUTPUT ;
    USE SIGNAL ;
    PORT
      LAYER M4 ;
        RECT  0 30.96 0.084 30.984 ;
    END
  END b[86]
  PIN b[87]
    DIRECTION OUTPUT ;
    USE SIGNAL ;
    PORT
      LAYER M4 ;
        RECT  0 31.056 0.084 31.08 ;
    END
  END b[87]
  PIN b[88]
    DIRECTION OUTPUT ;
    USE SIGNAL ;
    PORT
      LAYER M4 ;
        RECT  0 31.152 0.084 31.176 ;
    END
  END b[88]
  PIN b[89]
    DIRECTION OUTPUT ;
    USE SIGNAL ;
    PORT
      LAYER M4 ;
        RECT  0 31.248 0.084 31.272 ;
    END
  END b[89]
  PIN b[8]
    DIRECTION OUTPUT ;
    USE SIGNAL ;
    PORT
      LAYER M4 ;
        RECT  0 26.544 0.084 26.568 ;
    END
  END b[8]
  PIN b[90]
    DIRECTION OUTPUT ;
    USE SIGNAL ;
    PORT
      LAYER M4 ;
        RECT  0 31.344 0.084 31.368 ;
    END
  END b[90]
  PIN b[91]
    DIRECTION OUTPUT ;
    USE SIGNAL ;
    PORT
      LAYER M4 ;
        RECT  0 31.44 0.084 31.464 ;
    END
  END b[91]
  PIN b[92]
    DIRECTION OUTPUT ;
    USE SIGNAL ;
    PORT
      LAYER M4 ;
        RECT  0 31.536 0.084 31.56 ;
    END
  END b[92]
  PIN b[93]
    DIRECTION OUTPUT ;
    USE SIGNAL ;
    PORT
      LAYER M4 ;
        RECT  0 31.632 0.084 31.656 ;
    END
  END b[93]
  PIN b[94]
    DIRECTION OUTPUT ;
    USE SIGNAL ;
    PORT
      LAYER M4 ;
        RECT  0 31.728 0.084 31.752 ;
    END
  END b[94]
  PIN b[95]
    DIRECTION OUTPUT ;
    USE SIGNAL ;
    PORT
      LAYER M4 ;
        RECT  0 31.824 0.084 31.848 ;
    END
  END b[95]
  PIN b[96]
    DIRECTION OUTPUT ;
    USE SIGNAL ;
    PORT
      LAYER M4 ;
        RECT  0 37.68 0.084 37.704 ;
    END
  END b[96]
  PIN b[97]
    DIRECTION OUTPUT ;
    USE SIGNAL ;
    PORT
      LAYER M4 ;
        RECT  0 37.776 0.084 37.8 ;
    END
  END b[97]
  PIN b[98]
    DIRECTION OUTPUT ;
    USE SIGNAL ;
    PORT
      LAYER M4 ;
        RECT  0 37.872 0.084 37.896 ;
    END
  END b[98]
  PIN b[99]
    DIRECTION OUTPUT ;
    USE SIGNAL ;
    PORT
      LAYER M4 ;
        RECT  0 37.968 0.084 37.992 ;
    END
  END b[99]
  PIN b[9]
    DIRECTION OUTPUT ;
    USE SIGNAL ;
    PORT
      LAYER M4 ;
        RECT  0 26.64 0.084 26.664 ;
    END
  END b[9]
  PIN ck
    DIRECTION INPUT ;
    USE SIGNAL ;
    PORT
      LAYER M3 ;
        RECT  13.788 51.803 13.806 51.84 ;
    END
  END ck
  PIN ck_s
    DIRECTION INPUT ;
    USE SIGNAL ;
    PORT
      LAYER M3 ;
        RECT  13.86 51.803 13.878 51.84 ;
    END
  END ck_s
  PIN en
    DIRECTION INPUT ;
    USE SIGNAL ;
    PORT
      LAYER M3 ;
        RECT  13.932 51.803 13.95 51.84 ;
    END
  END en
  PIN fault
    DIRECTION OUTPUT ;
    USE SIGNAL ;
    PORT
      LAYER M3 ;
        RECT  14.004 51.803 14.022 51.84 ;
    END
  END fault
  PIN k0
    DIRECTION INPUT ;
    USE SIGNAL ;
    PORT
      LAYER M3 ;
        RECT  14.076 51.803 14.094 51.84 ;
    END
  END k0
  PIN k1
    DIRECTION INPUT ;
    USE SIGNAL ;
    PORT
      LAYER M3 ;
        RECT  14.148 51.803 14.166 51.84 ;
    END
  END k1
  PIN k2
    DIRECTION INPUT ;
    USE SIGNAL ;
    PORT
      LAYER M3 ;
        RECT  14.22 51.803 14.238 51.84 ;
    END
  END k2
  PIN k3
    DIRECTION INPUT ;
    USE SIGNAL ;
    PORT
      LAYER M3 ;
        RECT  14.292 51.803 14.31 51.84 ;
    END
  END k3
  PIN rs
    DIRECTION INPUT ;
    USE SIGNAL ;
    PORT
      LAYER M3 ;
        RECT  14.364 51.803 14.382 51.84 ;
    END
  END rs
  PIN tie_hi
    DIRECTION OUTPUT ;
    USE SIGNAL ;
    PORT
      LAYER M3 ;
        RECT  14.436 51.803 14.454 51.84 ;
    END
  END tie_hi
  PIN tie_lo
    DIRECTION OUTPUT ;
    USE SIGNAL ;
    PORT
      LAYER M3 ;
        RECT  14.508 51.803 14.526 51.84 ;
    END
  END tie_lo
  PIN VSS
    DIRECTION INOUT ;
    USE GROUND ;
    PORT
      LAYER M5 ;
        RECT  48.3 2.137 48.42 49.703 ;
        RECT  45.6 2.137 45.72 49.703 ;
        RECT  42.9 2.137 43.02 49.703 ;
        RECT  40.2 2.137 40.32 49.703 ;
        RECT  37.5 2.137 37.62 49.703 ;
        RECT  34.8 2.137 34.92 49.703 ;
        RECT  32.1 2.137 32.22 49.703 ;
        RECT  29.4 2.137 29.52 49.703 ;
        RECT  26.7 2.137 26.82 49.703 ;
        RECT  24 2.137 24.12 49.703 ;
        RECT  21.3 2.137 21.42 49.703 ;
        RECT  18.6 2.137 18.72 49.703 ;
        RECT  15.9 2.137 16.02 49.703 ;
        RECT  13.2 2.137 13.32 49.703 ;
        RECT  10.5 2.137 10.62 49.703 ;
        RECT  7.8 2.137 7.92 49.703 ;
        RECT  5.1 2.137 5.22 49.703 ;
        RECT  2.4 2.137 2.52 49.703 ;
    END
  END VSS
  PIN VDD
    DIRECTION INOUT ;
    USE POWER ;
    PORT
      LAYER M5 ;
        RECT  48.492 2.151 48.612 49.689 ;
        RECT  45.792 2.151 45.912 49.689 ;
        RECT  43.092 2.151 43.212 49.689 ;
        RECT  40.392 2.151 40.512 49.689 ;
        RECT  37.692 2.151 37.812 49.689 ;
        RECT  34.992 2.151 35.112 49.689 ;
        RECT  32.292 2.151 32.412 49.689 ;
        RECT  29.592 2.151 29.712 49.689 ;
        RECT  26.892 2.151 27.012 49.689 ;
        RECT  24.192 2.151 24.312 49.689 ;
        RECT  21.492 2.151 21.612 49.689 ;
        RECT  18.792 2.151 18.912 49.689 ;
        RECT  16.092 2.151 16.212 49.689 ;
        RECT  13.392 2.151 13.512 49.689 ;
        RECT  10.692 2.151 10.812 49.689 ;
        RECT  7.992 2.151 8.112 49.689 ;
        RECT  5.292 2.151 5.412 49.689 ;
        RECT  2.592 2.151 2.712 49.689 ;
    END
  END VDD
  OBS
    LAYER RVTN ;
     RECT  2.16 2.16 49.68 2.295 ;
     RECT  2.16 2.565 49.68 2.835 ;
     RECT  2.16 3.105 49.68 3.375 ;
     RECT  2.16 3.645 49.68 3.915 ;
     RECT  2.16 4.185 49.68 4.455 ;
     RECT  2.16 4.725 49.68 4.995 ;
     RECT  2.16 5.265 49.68 5.535 ;
     RECT  2.16 5.805 49.68 6.075 ;
     RECT  2.16 6.345 49.68 6.615 ;
     RECT  2.16 6.885 49.68 7.155 ;
     RECT  2.16 7.425 49.68 7.695 ;
     RECT  2.16 7.965 49.68 8.235 ;
     RECT  2.16 8.505 49.68 8.775 ;
     RECT  2.16 9.045 49.68 9.315 ;
     RECT  2.16 9.585 49.68 9.855 ;
     RECT  2.16 10.125 49.68 10.395 ;
     RECT  2.16 10.665 49.68 10.935 ;
     RECT  2.16 11.205 49.68 11.475 ;
     RECT  2.16 11.745 49.68 12.015 ;
     RECT  2.16 12.285 49.68 12.555 ;
     RECT  2.16 12.825 49.68 13.095 ;
     RECT  2.16 13.365 49.68 13.635 ;
     RECT  2.16 13.905 49.68 14.175 ;
     RECT  2.16 14.445 49.68 14.715 ;
     RECT  2.16 14.985 49.68 15.255 ;
     RECT  2.16 15.525 49.68 15.795 ;
     RECT  2.16 16.065 49.68 16.335 ;
     RECT  2.16 16.605 49.68 16.875 ;
     RECT  2.16 17.145 49.68 17.415 ;
     RECT  2.16 17.685 49.68 17.955 ;
     RECT  2.16 18.225 49.68 18.495 ;
     RECT  2.16 18.765 49.68 19.035 ;
     RECT  2.16 19.305 49.68 19.575 ;
     RECT  2.16 19.845 49.68 20.115 ;
     RECT  2.16 20.385 49.68 20.655 ;
     RECT  2.16 20.925 49.68 21.195 ;
     RECT  2.16 21.465 49.68 21.735 ;
     RECT  2.16 22.005 49.68 22.275 ;
     RECT  2.16 22.545 49.68 22.815 ;
     RECT  2.16 23.085 49.68 23.355 ;
     RECT  2.16 23.625 49.68 23.895 ;
     RECT  2.16 24.165 49.68 24.435 ;
     RECT  2.16 24.705 49.68 24.975 ;
     RECT  2.16 25.245 49.68 25.515 ;
     RECT  2.16 25.785 49.68 26.055 ;
     RECT  2.16 26.325 49.68 26.595 ;
     RECT  2.16 26.865 49.68 27.135 ;
     RECT  2.16 27.405 49.68 27.675 ;
     RECT  2.16 27.945 49.68 28.215 ;
     RECT  2.16 28.485 49.68 28.755 ;
     RECT  2.16 29.025 49.68 29.295 ;
     RECT  2.16 29.565 49.68 29.835 ;
     RECT  2.16 30.105 49.68 30.375 ;
     RECT  2.16 30.645 49.68 30.915 ;
     RECT  2.16 31.185 49.68 31.455 ;
     RECT  2.16 31.725 49.68 31.995 ;
     RECT  2.16 32.265 49.68 32.535 ;
     RECT  2.16 32.805 49.68 33.075 ;
     RECT  2.16 33.345 49.68 33.615 ;
     RECT  2.16 33.885 49.68 34.155 ;
     RECT  2.16 34.425 49.68 34.695 ;
     RECT  2.16 34.965 49.68 35.235 ;
     RECT  2.16 35.505 49.68 35.775 ;
     RECT  2.16 36.045 49.68 36.315 ;
     RECT  2.16 36.585 49.68 36.855 ;
     RECT  2.16 37.125 49.68 37.395 ;
     RECT  2.16 37.665 49.68 37.935 ;
     RECT  2.16 38.205 49.68 38.475 ;
     RECT  2.16 38.745 49.68 39.015 ;
     RECT  2.16 39.285 49.68 39.555 ;
     RECT  2.16 39.825 49.68 40.095 ;
     RECT  2.16 40.365 49.68 40.635 ;
     RECT  2.16 40.905 49.68 41.175 ;
     RECT  2.16 41.445 49.68 41.715 ;
     RECT  2.16 41.985 49.68 42.255 ;
     RECT  2.16 42.525 49.68 42.795 ;
     RECT  2.16 43.065 49.68 43.335 ;
     RECT  2.16 43.605 49.68 43.875 ;
     RECT  2.16 44.145 49.68 44.415 ;
     RECT  2.16 44.685 49.68 44.955 ;
     RECT  2.16 45.225 49.68 45.495 ;
     RECT  2.16 45.765 49.68 46.035 ;
     RECT  2.16 46.305 49.68 46.575 ;
     RECT  2.16 46.845 49.68 47.115 ;
     RECT  2.16 47.385 49.68 47.655 ;
     RECT  2.16 47.925 49.68 48.195 ;
     RECT  2.16 48.465 49.68 48.735 ;
     RECT  2.16 49.005 49.68 49.275 ;
     RECT  2.16 49.545 49.68 49.68 ;
    LAYER RVTP ;
     RECT  2.16 2.295 49.68 2.565 ;
     RECT  2.16 2.835 49.68 3.105 ;
     RECT  2.16 3.375 49.68 3.645 ;
     RECT  2.16 3.915 49.68 4.185 ;
     RECT  2.16 4.455 49.68 4.725 ;
     RECT  2.16 4.995 49.68 5.265 ;
     RECT  2.16 5.535 49.68 5.805 ;
     RECT  2.16 6.075 49.68 6.345 ;
     RECT  2.16 6.615 49.68 6.885 ;
     RECT  2.16 7.155 49.68 7.425 ;
     RECT  2.16 7.695 49.68 7.965 ;
     RECT  2.16 8.235 49.68 8.505 ;
     RECT  2.16 8.775 49.68 9.045 ;
     RECT  2.16 9.315 49.68 9.585 ;
     RECT  2.16 9.855 49.68 10.125 ;
     RECT  2.16 10.395 49.68 10.665 ;
     RECT  2.16 10.935 49.68 11.205 ;
     RECT  2.16 11.475 49.68 11.745 ;
     RECT  2.16 12.015 49.68 12.285 ;
     RECT  2.16 12.555 49.68 12.825 ;
     RECT  2.16 13.095 49.68 13.365 ;
     RECT  2.16 13.635 49.68 13.905 ;
     RECT  2.16 14.175 49.68 14.445 ;
     RECT  2.16 14.715 49.68 14.985 ;
     RECT  2.16 15.255 49.68 15.525 ;
     RECT  2.16 15.795 49.68 16.065 ;
     RECT  2.16 16.335 49.68 16.605 ;
     RECT  2.16 16.875 49.68 17.145 ;
     RECT  2.16 17.415 49.68 17.685 ;
     RECT  2.16 17.955 49.68 18.225 ;
     RECT  2.16 18.495 49.68 18.765 ;
     RECT  2.16 19.035 49.68 19.305 ;
     RECT  2.16 19.575 49.68 19.845 ;
     RECT  2.16 20.115 49.68 20.385 ;
     RECT  2.16 20.655 49.68 20.925 ;
     RECT  2.16 21.195 49.68 21.465 ;
     RECT  2.16 21.735 49.68 22.005 ;
     RECT  2.16 22.275 49.68 22.545 ;
     RECT  2.16 22.815 49.68 23.085 ;
     RECT  2.16 23.355 49.68 23.625 ;
     RECT  2.16 23.895 49.68 24.165 ;
     RECT  2.16 24.435 49.68 24.705 ;
     RECT  2.16 24.975 49.68 25.245 ;
     RECT  2.16 25.515 49.68 25.785 ;
     RECT  2.16 26.055 49.68 26.325 ;
     RECT  2.16 26.595 49.68 26.865 ;
     RECT  2.16 27.135 49.68 27.405 ;
     RECT  2.16 27.675 49.68 27.945 ;
     RECT  2.16 28.215 49.68 28.485 ;
     RECT  2.16 28.755 49.68 29.025 ;
     RECT  2.16 29.295 49.68 29.565 ;
     RECT  2.16 29.835 49.68 30.105 ;
     RECT  2.16 30.375 49.68 30.645 ;
     RECT  2.16 30.915 49.68 31.185 ;
     RECT  2.16 31.455 49.68 31.725 ;
     RECT  2.16 31.995 49.68 32.265 ;
     RECT  2.16 32.535 49.68 32.805 ;
     RECT  2.16 33.075 49.68 33.345 ;
     RECT  2.16 33.615 49.68 33.885 ;
     RECT  2.16 34.155 49.68 34.425 ;
     RECT  2.16 34.695 49.68 34.965 ;
     RECT  2.16 35.235 49.68 35.505 ;
     RECT  2.16 35.775 49.68 36.045 ;
     RECT  2.16 36.315 49.68 36.585 ;
     RECT  2.16 36.855 49.68 37.125 ;
     RECT  2.16 37.395 49.68 37.665 ;
     RECT  2.16 37.935 49.68 38.205 ;
     RECT  2.16 38.475 49.68 38.745 ;
     RECT  2.16 39.015 49.68 39.285 ;
     RECT  2.16 39.555 49.68 39.825 ;
     RECT  2.16 40.095 49.68 40.365 ;
     RECT  2.16 40.635 49.68 40.905 ;
     RECT  2.16 41.175 49.68 41.445 ;
     RECT  2.16 41.715 49.68 41.985 ;
     RECT  2.16 42.255 49.68 42.525 ;
     RECT  2.16 42.795 49.68 43.065 ;
     RECT  2.16 43.335 49.68 43.605 ;
     RECT  2.16 43.875 49.68 44.145 ;
     RECT  2.16 44.415 49.68 44.685 ;
     RECT  2.16 44.955 49.68 45.225 ;
     RECT  2.16 45.495 49.68 45.765 ;
     RECT  2.16 46.035 49.68 46.305 ;
     RECT  2.16 46.575 49.68 46.845 ;
     RECT  2.16 47.115 49.68 47.385 ;
     RECT  2.16 47.655 49.68 47.925 ;
     RECT  2.16 48.195 49.68 48.465 ;
     RECT  2.16 48.735 49.68 49.005 ;
     RECT  2.16 49.275 49.68 49.545 ;
    LAYER M1 ;
     RECT  2.16 2.151 49.68 49.689 ;
    LAYER M2 ;
     RECT  0.103 30.726 0.139 30.744 ;
     RECT  0.103 32.076 0.139 32.094 ;
     RECT  0.103 14.454 0.203 14.472 ;
     RECT  0.139 30.186 0.203 30.744 ;
     RECT  0.203 30.186 0.239 30.204 ;
     RECT  0.103 39.096 0.347 39.114 ;
     RECT  0.103 25.596 0.427 25.884 ;
     RECT  0.103 27.144 0.427 27.162 ;
     RECT  0.427 25.29 0.463 27.162 ;
     RECT  0.103 27.918 0.463 27.936 ;
     RECT  0.103 37.566 0.499 37.584 ;
     RECT  0.499 13.644 0.535 13.662 ;
     RECT  0.463 25.29 0.535 27.936 ;
     RECT  0.499 37.566 0.535 37.656 ;
     RECT  0.139 32.004 1.039 32.094 ;
     RECT  1.039 31.734 1.147 32.094 ;
     RECT  0.535 13.536 2.16 13.662 ;
     RECT  0.535 25.29 2.16 28.476 ;
     RECT  1.147 31.734 2.16 32.364 ;
     RECT  0.535 37.566 2.16 37.926 ;
     RECT  14.143 50.751 14.287 50.769 ;
     RECT  14.287 50.751 14.315 50.85 ;
     RECT  14.315 50.796 14.531 50.85 ;
     RECT  14.531 50.832 15.287 50.85 ;
     RECT  2.16 2.151 30.631 49.689 ;
     RECT  30.631 2.106 31.559 49.689 ;
     RECT  31.559 2.151 34.771 49.689 ;
     RECT  34.771 2.106 36.275 49.689 ;
     RECT  36.275 2.151 42.871 49.689 ;
     RECT  42.871 2.106 43.079 49.689 ;
     RECT  43.079 2.151 49.68 49.689 ;
     RECT  49.68 6.696 49.883 8.298 ;
     RECT  49.68 18.576 49.883 18.594 ;
     RECT  49.68 11.754 49.919 12.888 ;
     RECT  49.68 22.05 49.919 22.608 ;
     RECT  49.883 7.506 49.955 8.298 ;
     RECT  49.68 34.506 49.955 34.524 ;
     RECT  49.68 13.95 49.991 16.092 ;
     RECT  49.68 9.054 50.027 9.108 ;
     RECT  49.68 32.616 50.027 32.634 ;
     RECT  49.68 24.246 50.063 24.804 ;
     RECT  49.991 14.49 50.243 16.092 ;
     RECT  50.243 14.49 50.279 15.624 ;
     RECT  49.919 11.754 50.459 12.384 ;
     RECT  49.68 17.226 50.459 17.784 ;
     RECT  49.955 7.938 50.495 8.298 ;
     RECT  49.68 19.656 50.495 19.674 ;
     RECT  50.279 14.49 50.567 15.318 ;
     RECT  49.919 22.59 50.567 22.608 ;
     RECT  50.567 15.03 50.603 15.318 ;
     RECT  50.063 24.786 50.603 24.804 ;
     RECT  49.68 31.806 50.639 31.824 ;
     RECT  49.68 26.676 50.675 30.978 ;
     RECT  50.675 30.456 50.711 30.978 ;
     RECT  50.459 17.226 50.747 17.244 ;
     RECT  49.68 25.866 50.747 25.884 ;
     RECT  50.675 26.676 50.747 29.556 ;
     RECT  50.711 30.456 50.747 30.474 ;
     RECT  49.68 41.796 50.747 41.814 ;
     RECT  50.747 27.99 50.783 29.556 ;
     RECT  49.68 42.732 50.783 44.334 ;
     RECT  50.783 27.99 50.819 28.008 ;
     RECT  50.783 42.876 50.819 44.208 ;
     RECT  50.603 15.3 51.539 15.318 ;
     RECT  50.819 43.11 51.575 44.208 ;
     RECT  50.459 11.79 51.647 12.384 ;
     RECT  50.747 26.676 51.655 26.694 ;
     RECT  50.783 28.836 51.655 29.556 ;
     RECT  51.655 28.836 51.683 30.204 ;
     RECT  51.575 43.11 51.683 43.164 ;
     RECT  51.647 11.79 51.719 11.808 ;
     RECT  51.683 29.034 51.719 30.204 ;
     RECT  51.691 18.162 51.727 18.18 ;
     RECT  50.495 7.938 51.755 7.956 ;
     RECT  51.583 14.841 51.755 14.859 ;
     RECT  51.655 16.92 51.755 16.938 ;
     RECT  51.655 26.136 51.755 27.234 ;
     RECT  51.719 29.538 51.755 30.204 ;
     RECT  51.655 31.356 51.755 31.824 ;
     RECT  51.683 43.11 51.755 43.128 ;
     RECT  51.575 44.19 51.755 44.208 ;
     RECT  50.027 9.054 51.791 9.072 ;
     RECT  51.727 18.162 51.791 18.288 ;
     RECT  49.883 6.696 51.827 6.714 ;
     RECT  51.791 18.27 51.827 18.288 ;
    LAYER M3 ;
     RECT  31.536 2.101 31.554 2.143 ;
     RECT  34.776 2.101 34.794 2.143 ;
     RECT  5.115 2.143 5.205 2.191 ;
     RECT  13.215 2.143 13.305 2.191 ;
     RECT  18.615 2.143 18.705 2.191 ;
     RECT  30.636 2.101 30.654 2.191 ;
     RECT  34.776 2.143 34.905 2.191 ;
     RECT  42.876 2.101 43.074 2.191 ;
     RECT  6.408 2.191 6.426 2.227 ;
     RECT  36.252 2.101 36.27 2.227 ;
     RECT  45.615 2.143 45.705 2.227 ;
     RECT  6.408 2.227 7.002 2.251 ;
     RECT  8.82 2.227 9.45 2.251 ;
     RECT  34.38 2.191 34.905 2.251 ;
     RECT  40.215 2.143 40.305 2.251 ;
     RECT  41.796 2.191 41.814 2.251 ;
     RECT  42.876 2.191 43.47 2.251 ;
     RECT  46.8 2.191 46.818 2.251 ;
     RECT  8.784 2.251 9.45 2.263 ;
     RECT  25.956 2.227 25.974 2.263 ;
     RECT  26.715 2.143 26.805 2.263 ;
     RECT  27.576 2.227 27.954 2.263 ;
     RECT  34.38 2.251 35.406 2.263 ;
     RECT  37.515 2.143 37.605 2.263 ;
     RECT  38.916 2.227 38.934 2.263 ;
     RECT  44.208 2.227 44.226 2.263 ;
     RECT  45 2.227 45.705 2.263 ;
     RECT  44.208 2.263 45.705 2.285 ;
     RECT  13.215 2.191 13.77 2.299 ;
     RECT  15.915 2.143 16.005 2.299 ;
     RECT  17.784 2.251 17.802 2.299 ;
     RECT  18.615 2.191 19.098 2.299 ;
     RECT  20.16 2.263 20.178 2.299 ;
     RECT  21.315 2.143 21.405 2.299 ;
     RECT  22.212 2.191 22.23 2.299 ;
     RECT  30.636 2.191 30.798 2.299 ;
     RECT  31.536 2.143 32.205 2.299 ;
     RECT  33.768 2.263 35.406 2.299 ;
     RECT  38.916 2.263 39.366 2.299 ;
     RECT  10.515 2.143 10.605 2.327 ;
     RECT  6.012 2.251 7.002 2.335 ;
     RECT  7.815 2.143 7.905 2.335 ;
     RECT  11.664 2.299 11.682 2.335 ;
     RECT  13.032 2.299 13.77 2.335 ;
     RECT  15.915 2.299 16.038 2.335 ;
     RECT  21.132 2.299 22.518 2.335 ;
     RECT  30.564 2.299 32.205 2.335 ;
     RECT  37.404 2.263 37.605 2.335 ;
     RECT  38.376 2.299 39.366 2.335 ;
     RECT  11.52 2.335 11.682 2.347 ;
     RECT  5.004 2.191 5.205 2.371 ;
     RECT  6.012 2.335 7.905 2.371 ;
     RECT  8.784 2.263 9.594 2.371 ;
     RECT  10.512 2.327 10.605 2.371 ;
     RECT  11.52 2.347 12.114 2.371 ;
     RECT  13.032 2.335 14.238 2.371 ;
     RECT  15.264 2.335 16.074 2.371 ;
     RECT  17.784 2.299 19.098 2.371 ;
     RECT  19.872 2.299 20.178 2.371 ;
     RECT  20.916 2.335 22.914 2.371 ;
     RECT  25.956 2.263 26.805 2.371 ;
     RECT  27.576 2.263 28.458 2.371 ;
     RECT  29.415 2.143 29.505 2.371 ;
     RECT  30.276 2.335 32.205 2.371 ;
     RECT  33.156 2.299 35.406 2.371 ;
     RECT  36.144 2.227 36.27 2.371 ;
     RECT  37.404 2.335 39.366 2.371 ;
     RECT  40.215 2.251 40.59 2.371 ;
     RECT  41.328 2.251 43.47 2.371 ;
     RECT  46.512 2.251 46.818 2.371 ;
     RECT  30.276 2.371 43.47 2.395 ;
     RECT  2.415 2.143 2.505 2.413 ;
     RECT  24.015 2.143 24.105 2.413 ;
     RECT  25.956 2.371 29.505 2.413 ;
     RECT  30.24 2.395 43.47 2.413 ;
     RECT  44.388 2.285 45.705 2.413 ;
     RECT  46.512 2.371 47.502 2.413 ;
     RECT  48.315 2.143 48.405 2.413 ;
     RECT  19.872 2.371 23.13 2.461 ;
     RECT  24.015 2.413 24.297 2.461 ;
     RECT  17.784 2.371 19.134 2.491 ;
     RECT  19.872 2.461 24.297 2.491 ;
     RECT  13.032 2.371 16.542 2.497 ;
     RECT  5.004 2.371 9.594 2.569 ;
     RECT  17.784 2.491 24.297 2.569 ;
     RECT  25.956 2.413 43.47 2.569 ;
     RECT  2.415 2.413 2.697 2.605 ;
     RECT  2.415 2.605 2.754 2.641 ;
     RECT  4.788 2.569 9.594 2.641 ;
     RECT  10.368 2.371 12.114 2.641 ;
     RECT  12.924 2.497 16.542 2.641 ;
     RECT  17.46 2.569 24.426 2.641 ;
     RECT  44.388 2.413 47.502 2.641 ;
     RECT  48.315 2.413 48.597 2.641 ;
     RECT  25.92 2.569 43.47 2.669 ;
     RECT  3.96 2.227 3.978 2.731 ;
     RECT  4.788 2.641 24.426 2.731 ;
     RECT  3.96 2.731 24.426 2.767 ;
     RECT  2.415 2.641 2.862 2.803 ;
     RECT  3.96 2.767 24.786 2.803 ;
     RECT  2.415 2.803 25.074 2.911 ;
     RECT  25.92 2.669 36.27 2.911 ;
     RECT  44.388 2.641 48.69 2.911 ;
     RECT  37.08 2.669 43.47 3.001 ;
     RECT  2.415 2.911 36.27 3.065 ;
     RECT  2.415 3.065 3.438 3.101 ;
     RECT  37.08 3.001 43.578 3.145 ;
     RECT  44.388 2.911 48.726 3.145 ;
     RECT  31.824 3.065 36.27 3.403 ;
     RECT  37.08 3.145 48.726 3.403 ;
     RECT  31.824 3.403 48.726 3.721 ;
     RECT  15.915 3.065 31.05 3.811 ;
     RECT  31.824 3.721 49.23 3.811 ;
     RECT  2.415 3.101 3.402 3.955 ;
     RECT  4.176 3.065 14.886 3.955 ;
     RECT  15.915 3.811 49.23 4.145 ;
     RECT  2.415 3.955 14.886 4.261 ;
     RECT  15.915 4.145 48.762 4.387 ;
     RECT  2.415 4.261 15.03 4.621 ;
     RECT  15.804 4.387 48.762 4.621 ;
     RECT  2.415 4.621 48.762 5.035 ;
     RECT  2.415 5.035 49.05 5.069 ;
     RECT  2.415 5.069 15.066 5.189 ;
     RECT  7.308 5.189 14.886 5.225 ;
     RECT  15.804 5.069 49.05 5.305 ;
     RECT  15.804 5.305 49.122 5.333 ;
     RECT  20.16 5.333 49.122 5.341 ;
     RECT  15.804 5.333 19.422 5.459 ;
     RECT  20.16 5.341 49.194 5.459 ;
     RECT  20.844 5.459 49.194 5.801 ;
     RECT  20.844 5.801 49.122 5.873 ;
     RECT  7.308 5.225 14.85 6.035 ;
     RECT  27.864 5.873 49.122 6.035 ;
     RECT  15.876 5.459 19.422 6.071 ;
     RECT  2.415 5.189 6.534 6.079 ;
     RECT  7.308 6.035 8.226 6.079 ;
     RECT  27.9 6.035 49.122 6.269 ;
     RECT  19.836 6.115 19.854 6.283 ;
     RECT  19.836 6.283 20.034 6.313 ;
     RECT  20.844 5.873 27.126 6.313 ;
     RECT  8.964 6.035 14.85 6.349 ;
     RECT  8.964 6.349 14.886 6.539 ;
     RECT  19.836 6.313 27.126 6.781 ;
     RECT  27.9 6.269 48.69 6.781 ;
     RECT  19.836 6.781 48.69 6.809 ;
     RECT  2.415 6.079 8.226 6.817 ;
     RECT  8.964 6.539 14.706 6.817 ;
     RECT  15.876 6.071 18.99 6.817 ;
     RECT  2.415 6.817 14.706 7.087 ;
     RECT  39.888 6.809 48.69 7.087 ;
     RECT  49.86 6.961 49.878 7.087 ;
     RECT  15.552 6.817 18.99 7.231 ;
     RECT  19.836 6.809 39.078 7.231 ;
     RECT  2.376 7.087 14.706 7.393 ;
     RECT  15.552 7.231 39.078 7.393 ;
     RECT  2.376 7.393 39.078 7.493 ;
     RECT  39.888 7.087 49.878 7.501 ;
     RECT  33.516 7.493 39.078 7.591 ;
     RECT  33.516 7.591 39.15 7.771 ;
     RECT  39.888 7.501 49.95 7.771 ;
     RECT  33.516 7.771 49.95 7.889 ;
     RECT  2.376 7.493 32.778 7.925 ;
     RECT  33.516 7.889 44.19 7.925 ;
     RECT  51.804 6.691 51.822 7.933 ;
     RECT  2.376 7.925 27.198 7.961 ;
     RECT  2.376 7.961 27.09 8.195 ;
     RECT  28.008 7.925 32.778 8.239 ;
     RECT  33.516 7.925 44.082 8.239 ;
     RECT  44.964 7.889 49.95 8.275 ;
     RECT  2.415 8.195 27.09 8.573 ;
     RECT  28.008 8.239 44.082 8.843 ;
     RECT  17.856 8.573 27.09 8.851 ;
     RECT  28.008 8.843 39.006 8.851 ;
     RECT  39.816 8.843 44.082 8.851 ;
     RECT  39.816 8.851 44.154 8.941 ;
     RECT  44.964 8.275 50.49 8.941 ;
     RECT  39.816 8.941 50.49 9.005 ;
     RECT  17.856 8.851 39.006 9.041 ;
     RECT  2.415 8.573 17.046 9.661 ;
     RECT  17.856 9.041 38.97 9.661 ;
     RECT  39.888 9.005 50.49 9.823 ;
     RECT  2.415 9.661 38.97 10.201 ;
     RECT  2.376 10.201 38.97 10.291 ;
     RECT  39.816 9.823 50.49 10.291 ;
     RECT  2.376 10.291 50.49 10.355 ;
     RECT  2.415 10.355 50.49 10.931 ;
     RECT  2.415 10.931 38.898 10.967 ;
     RECT  2.415 10.967 37.797 11.435 ;
     RECT  38.736 10.967 38.898 11.677 ;
     RECT  39.636 10.931 50.49 11.677 ;
     RECT  36.18 11.435 37.797 11.749 ;
     RECT  38.736 11.677 50.49 11.749 ;
     RECT  51.732 7.933 51.822 11.785 ;
     RECT  36.18 11.749 50.49 12.091 ;
     RECT  2.415 11.435 35.406 12.181 ;
     RECT  36.18 12.091 50.526 12.181 ;
     RECT  51.696 11.785 51.822 12.361 ;
     RECT  2.415 12.181 50.526 13.441 ;
     RECT  2.304 13.441 50.526 13.517 ;
     RECT  0.54 13.531 0.558 13.639 ;
     RECT  0.504 13.639 0.558 13.805 ;
     RECT  0.504 13.805 0.522 13.819 ;
     RECT  0.144 13.819 0.522 14.449 ;
     RECT  2.415 13.517 50.526 14.485 ;
     RECT  0.108 14.449 0.522 14.573 ;
     RECT  2.415 14.485 50.562 14.639 ;
     RECT  7.2 14.639 50.562 14.711 ;
     RECT  2.415 14.639 6.462 14.731 ;
     RECT  51.624 12.361 51.822 14.836 ;
     RECT  0.504 14.573 0.522 14.861 ;
     RECT  7.38 14.711 50.562 15.025 ;
     RECT  7.38 15.025 50.598 15.089 ;
     RECT  2.304 14.731 6.462 15.197 ;
     RECT  51.588 14.836 51.822 15.295 ;
     RECT  9.792 15.089 50.598 15.359 ;
     RECT  3.42 15.197 6.462 15.449 ;
     RECT  3.456 15.449 6.462 15.529 ;
     RECT  3.456 15.529 6.534 15.601 ;
     RECT  7.38 15.089 9.054 15.601 ;
     RECT  1.44 15.595 1.458 15.643 ;
     RECT  1.152 15.643 1.458 15.773 ;
     RECT  1.152 15.773 1.386 15.821 ;
     RECT  3.456 15.601 9.054 15.997 ;
     RECT  9.792 15.359 41.634 15.997 ;
     RECT  2.304 15.197 2.697 16.339 ;
     RECT  3.456 15.997 41.634 16.339 ;
     RECT  42.372 15.359 50.598 16.339 ;
     RECT  2.304 16.339 50.598 16.367 ;
     RECT  2.34 16.367 50.598 16.589 ;
     RECT  2.34 16.589 20.142 17.069 ;
     RECT  20.88 16.589 50.598 17.105 ;
     RECT  20.88 17.105 41.958 17.213 ;
     RECT  42.696 17.105 50.598 17.221 ;
     RECT  20.952 17.213 41.958 17.339 ;
     RECT  2.415 17.069 20.142 17.383 ;
     RECT  20.988 17.339 41.958 17.447 ;
     RECT  42.696 17.221 50.742 17.645 ;
     RECT  2.415 17.383 20.178 17.951 ;
     RECT  21.132 17.447 41.958 18.031 ;
     RECT  42.696 17.645 50.598 18.031 ;
     RECT  12.528 17.951 20.178 18.235 ;
     RECT  21.132 18.031 50.598 18.235 ;
     RECT  51.516 15.295 51.822 18.293 ;
     RECT  51.516 18.293 51.75 18.317 ;
     RECT  51.516 18.317 51.606 18.605 ;
     RECT  51.516 18.605 51.534 18.893 ;
     RECT  12.528 18.235 50.598 18.989 ;
     RECT  12.528 18.989 50.49 19.103 ;
     RECT  2.415 17.951 11.79 19.273 ;
     RECT  12.528 19.103 49.014 19.273 ;
     RECT  2.415 19.273 49.014 19.301 ;
     RECT  11.7 19.301 49.014 19.337 ;
     RECT  42.516 19.337 49.014 19.535 ;
     RECT  42.588 19.535 49.014 19.885 ;
     RECT  49.86 19.103 50.49 19.885 ;
     RECT  11.7 19.337 41.778 20.039 ;
     RECT  2.415 19.301 10.797 20.059 ;
     RECT  2.376 20.059 10.797 20.309 ;
     RECT  42.588 19.885 50.49 20.345 ;
     RECT  42.588 20.345 48.978 20.659 ;
     RECT  11.7 20.039 41.67 20.731 ;
     RECT  2.415 20.309 10.797 20.893 ;
     RECT  11.628 20.731 41.67 20.893 ;
     RECT  2.415 20.893 41.67 20.965 ;
     RECT  42.444 20.659 48.978 20.965 ;
     RECT  2.415 20.965 48.978 21.541 ;
     RECT  49.86 20.345 50.49 21.541 ;
     RECT  2.415 21.541 50.49 22.585 ;
     RECT  2.415 22.585 50.562 23.161 ;
     RECT  2.376 23.161 50.562 23.165 ;
     RECT  2.376 23.165 25.65 23.351 ;
     RECT  26.424 23.165 50.562 23.585 ;
     RECT  2.415 23.351 25.65 23.935 ;
     RECT  26.424 23.585 39.474 23.935 ;
     RECT  2.415 23.935 39.474 24.331 ;
     RECT  40.212 23.585 50.562 24.331 ;
     RECT  2.415 24.331 50.562 24.781 ;
     RECT  0.432 25.285 0.45 25.447 ;
     RECT  0.432 25.447 0.522 25.591 ;
     RECT  0.108 25.591 0.522 25.861 ;
     RECT  2.415 24.781 50.598 25.861 ;
     RECT  0.108 25.861 0.558 25.901 ;
     RECT  2.415 25.861 50.742 26.093 ;
     RECT  51.66 26.107 51.678 26.131 ;
     RECT  51.66 26.131 51.75 26.443 ;
     RECT  2.415 26.093 50.598 26.789 ;
     RECT  0.144 25.901 0.558 26.827 ;
     RECT  38.808 26.789 50.598 26.827 ;
     RECT  2.415 26.789 38.07 26.941 ;
     RECT  38.808 26.827 50.634 26.941 ;
     RECT  0.144 26.827 0.63 26.957 ;
     RECT  0.144 26.957 0.558 27.139 ;
     RECT  38.808 26.941 50.742 27.365 ;
     RECT  2.376 26.941 38.07 27.389 ;
     RECT  51.624 26.443 51.75 27.677 ;
     RECT  2.376 27.389 38.034 27.877 ;
     RECT  38.916 27.365 50.742 27.985 ;
     RECT  0.108 27.139 0.558 28.205 ;
     RECT  38.916 27.985 50.814 28.205 ;
     RECT  2.34 27.877 38.034 28.211 ;
     RECT  38.916 28.205 50.778 28.255 ;
     RECT  32.115 28.211 38.034 28.489 ;
     RECT  38.772 28.255 50.778 28.489 ;
     RECT  2.34 28.211 31.374 28.552 ;
     RECT  32.115 28.489 50.778 28.589 ;
     RECT  51.732 27.677 51.75 28.651 ;
     RECT  2.304 28.552 31.374 28.688 ;
     RECT  51.696 28.651 51.75 28.747 ;
     RECT  51.66 28.747 51.75 28.843 ;
     RECT  2.376 28.688 31.374 28.859 ;
     RECT  32.115 28.589 50.742 28.973 ;
     RECT  51.624 28.843 51.75 29.131 ;
     RECT  0.54 28.205 0.558 29.165 ;
     RECT  4.572 28.859 31.374 29.191 ;
     RECT  32.115 28.973 50.634 29.191 ;
     RECT  4.572 29.191 50.634 29.219 ;
     RECT  51.516 29.131 51.75 29.261 ;
     RECT  51.588 29.261 51.75 29.309 ;
     RECT  6.84 29.219 50.634 29.363 ;
     RECT  38.592 29.363 50.634 29.525 ;
     RECT  2.415 28.859 2.697 29.611 ;
     RECT  3.492 28.859 3.69 29.611 ;
     RECT  2.415 29.611 3.69 29.641 ;
     RECT  4.572 29.219 6.102 29.641 ;
     RECT  2.415 29.641 6.102 29.707 ;
     RECT  0.144 29.419 0.162 29.995 ;
     RECT  38.772 29.525 50.634 30.001 ;
     RECT  2.304 29.707 6.102 30.139 ;
     RECT  6.84 29.363 37.854 30.139 ;
     RECT  51.66 29.309 51.75 30.221 ;
     RECT  1.26 30.283 1.278 30.379 ;
     RECT  1.152 30.379 1.278 30.413 ;
     RECT  2.304 30.139 37.854 30.451 ;
     RECT  38.772 30.001 50.67 30.451 ;
     RECT  51.66 30.221 51.678 30.461 ;
     RECT  0.144 29.995 0.342 30.571 ;
     RECT  0.108 30.571 0.342 30.893 ;
     RECT  2.304 30.451 50.742 31.019 ;
     RECT  51.588 30.907 51.606 31.181 ;
     RECT  1.152 30.413 1.17 31.627 ;
     RECT  0.108 30.893 0.198 31.709 ;
     RECT  1.152 31.627 1.278 31.729 ;
     RECT  1.044 31.729 1.278 31.757 ;
     RECT  2.376 31.019 50.742 31.757 ;
     RECT  2.376 31.757 50.634 31.801 ;
     RECT  2.304 31.801 50.634 31.829 ;
     RECT  51.66 31.339 51.75 31.829 ;
     RECT  1.044 31.757 1.242 31.853 ;
     RECT  2.304 31.829 50.526 31.853 ;
     RECT  51.732 31.829 51.75 31.853 ;
     RECT  2.376 31.853 50.526 31.919 ;
     RECT  0.108 31.709 0.162 32.027 ;
     RECT  0.108 32.027 0.126 32.099 ;
     RECT  1.152 31.853 1.242 32.099 ;
     RECT  2.415 31.919 50.526 32.189 ;
     RECT  1.152 32.099 1.17 32.369 ;
     RECT  3.816 32.189 50.526 32.573 ;
     RECT  3.816 32.573 50.022 32.639 ;
     RECT  2.415 32.189 3.042 32.971 ;
     RECT  3.816 32.639 49.95 32.971 ;
     RECT  2.415 32.971 49.95 34.385 ;
     RECT  2.415 34.385 49.05 34.501 ;
     RECT  49.932 34.385 49.95 34.529 ;
     RECT  2.376 34.501 49.05 34.619 ;
     RECT  2.415 34.619 49.05 35.311 ;
     RECT  2.415 35.311 49.158 35.465 ;
     RECT  2.415 35.465 49.014 35.879 ;
     RECT  26.64 35.879 49.014 36.041 ;
     RECT  2.415 35.879 25.866 36.661 ;
     RECT  26.64 36.041 48.942 36.661 ;
     RECT  2.415 36.661 48.942 36.779 ;
     RECT  4.608 36.779 48.942 37.085 ;
     RECT  26.64 37.085 48.942 37.327 ;
     RECT  26.64 37.327 48.978 37.399 ;
     RECT  26.64 37.399 49.194 37.463 ;
     RECT  2.415 36.779 3.618 37.561 ;
     RECT  4.608 37.085 25.902 37.561 ;
     RECT  2.415 37.561 25.902 37.589 ;
     RECT  2.415 37.589 5.994 37.625 ;
     RECT  0.108 37.561 0.126 37.633 ;
     RECT  26.715 37.463 49.194 37.741 ;
     RECT  0.108 37.633 0.522 37.805 ;
     RECT  0.144 37.805 0.522 37.903 ;
     RECT  6.732 37.589 25.902 38.137 ;
     RECT  6.732 38.137 25.974 38.201 ;
     RECT  0.144 37.903 0.558 38.285 ;
     RECT  6.732 38.201 25.722 38.371 ;
     RECT  0.144 38.285 0.522 38.381 ;
     RECT  26.715 37.741 49.482 38.435 ;
     RECT  2.415 37.625 5.85 38.479 ;
     RECT  6.696 38.371 25.722 38.573 ;
     RECT  26.715 38.435 40.554 38.587 ;
     RECT  26.712 38.587 40.554 38.669 ;
     RECT  26.712 38.669 35.154 38.705 ;
     RECT  41.472 38.435 49.482 38.749 ;
     RECT  2.415 38.479 5.922 38.785 ;
     RECT  6.696 38.573 25.686 38.785 ;
     RECT  26.712 38.705 35.097 38.821 ;
     RECT  2.415 38.785 25.686 38.827 ;
     RECT  41.472 38.749 49.554 38.939 ;
     RECT  0.144 38.381 0.342 39.019 ;
     RECT  41.472 38.939 49.014 39.083 ;
     RECT  0.108 39.019 0.342 39.119 ;
     RECT  41.472 39.083 48.726 39.209 ;
     RECT  0.18 39.119 0.342 39.245 ;
     RECT  41.472 39.209 48.654 39.245 ;
     RECT  0.18 39.245 0.198 39.293 ;
     RECT  41.472 39.245 48.597 39.293 ;
     RECT  2.304 38.827 25.686 39.361 ;
     RECT  26.46 38.821 35.097 39.361 ;
     RECT  2.304 39.361 35.097 39.437 ;
     RECT  2.415 39.437 35.097 39.451 ;
     RECT  35.928 38.669 40.554 39.451 ;
     RECT  2.415 39.451 40.554 39.485 ;
     RECT  2.415 39.485 4.122 39.749 ;
     RECT  4.86 39.485 40.554 39.901 ;
     RECT  4.86 39.901 40.698 40.063 ;
     RECT  4.86 40.063 41.022 40.171 ;
     RECT  41.832 39.293 48.597 40.171 ;
     RECT  49.32 40.099 49.338 40.171 ;
     RECT  4.86 40.171 49.338 40.289 ;
     RECT  4.032 39.749 4.122 40.297 ;
     RECT  4.86 40.289 48.942 40.297 ;
     RECT  4.032 40.297 48.942 40.325 ;
     RECT  2.415 39.749 3.042 40.567 ;
     RECT  4.032 40.325 48.618 40.567 ;
     RECT  2.415 40.567 48.618 40.829 ;
     RECT  2.415 40.829 44.046 41.099 ;
     RECT  44.82 40.829 48.618 41.099 ;
     RECT  44.928 41.099 48.618 41.143 ;
     RECT  44.928 41.143 48.726 41.179 ;
     RECT  2.415 41.099 43.938 41.215 ;
     RECT  44.928 41.179 48.834 41.449 ;
     RECT  44.928 41.449 48.978 41.521 ;
     RECT  44.928 41.521 49.122 42.061 ;
     RECT  2.376 41.215 43.938 42.151 ;
     RECT  44.928 42.061 49.266 42.151 ;
     RECT  2.376 42.151 49.266 42.449 ;
     RECT  2.415 42.449 49.266 42.565 ;
     RECT  50.724 41.791 50.742 42.727 ;
     RECT  50.724 42.727 50.778 42.871 ;
     RECT  50.724 42.871 50.814 42.955 ;
     RECT  50.724 42.955 51.534 43.085 ;
     RECT  51.552 43.099 51.606 43.105 ;
     RECT  2.415 42.565 49.41 43.645 ;
     RECT  50.724 43.085 50.814 43.645 ;
     RECT  2.376 43.645 49.41 43.681 ;
     RECT  50.184 43.645 50.814 43.681 ;
     RECT  2.376 43.681 50.814 43.757 ;
     RECT  50.184 43.757 50.814 43.949 ;
     RECT  51.552 43.105 51.75 44.213 ;
     RECT  2.376 43.757 49.014 44.249 ;
     RECT  50.724 43.949 50.814 44.333 ;
     RECT  50.724 44.333 50.778 44.429 ;
     RECT  51.552 44.213 51.678 44.669 ;
     RECT  51.552 44.669 51.57 44.717 ;
     RECT  2.415 44.249 49.014 44.761 ;
     RECT  50.76 44.429 50.778 44.813 ;
     RECT  2.415 44.761 49.482 44.915 ;
     RECT  2.415 44.915 49.014 45.491 ;
     RECT  36.468 45.491 49.014 46.031 ;
     RECT  36.468 46.031 48.762 46.229 ;
     RECT  49.536 46.075 49.554 46.229 ;
     RECT  2.415 45.491 35.73 46.345 ;
     RECT  36.468 46.229 48.726 46.345 ;
     RECT  2.415 46.345 48.726 46.679 ;
     RECT  38.664 46.679 48.726 47.011 ;
     RECT  2.415 46.679 37.797 47.075 ;
     RECT  38.664 47.011 48.87 47.309 ;
     RECT  20.376 47.075 37.797 47.461 ;
     RECT  38.664 47.309 48.798 47.461 ;
     RECT  20.376 47.461 48.798 47.489 ;
     RECT  2.415 47.075 19.602 47.857 ;
     RECT  20.376 47.489 48.726 47.857 ;
     RECT  2.415 47.857 48.726 48.001 ;
     RECT  2.376 48.001 48.726 48.271 ;
     RECT  2.376 48.271 48.978 48.505 ;
     RECT  2.376 48.505 49.554 48.659 ;
     RECT  2.376 48.659 49.23 48.839 ;
     RECT  2.376 48.839 38.358 48.929 ;
     RECT  39.348 48.839 49.23 48.929 ;
     RECT  19.728 48.929 38.358 48.965 ;
     RECT  39.348 48.929 39.366 48.965 ;
     RECT  19.728 48.965 27.27 48.989 ;
     RECT  2.376 48.929 18.954 49.001 ;
     RECT  2.376 49.001 18.897 49.109 ;
     RECT  2.376 49.109 11.862 49.199 ;
     RECT  12.636 49.109 18.897 49.199 ;
     RECT  19.8 48.989 27.27 49.199 ;
     RECT  40.14 48.929 49.23 49.199 ;
     RECT  19.8 49.199 22.014 49.229 ;
     RECT  2.376 49.199 11.826 49.235 ;
     RECT  28.116 48.965 38.214 49.235 ;
     RECT  34.056 49.235 38.214 49.271 ;
     RECT  40.215 49.199 49.23 49.271 ;
     RECT  22.86 49.199 27.27 49.307 ;
     RECT  29.052 49.235 33.102 49.307 ;
     RECT  40.215 49.271 48.597 49.307 ;
     RECT  19.836 49.229 22.014 49.343 ;
     RECT  31.104 49.307 32.706 49.343 ;
     RECT  34.056 49.271 37.797 49.379 ;
     RECT  40.215 49.307 44.874 49.379 ;
     RECT  45.612 49.307 48.597 49.379 ;
     RECT  12.672 49.199 18.897 49.427 ;
     RECT  22.86 49.307 26.997 49.427 ;
     RECT  34.272 49.379 37.797 49.427 ;
     RECT  40.215 49.379 43.362 49.427 ;
     RECT  48.315 49.379 48.597 49.427 ;
     RECT  2.376 49.235 9.738 49.469 ;
     RECT  10.515 49.235 11.826 49.469 ;
     RECT  12.672 49.427 16.005 49.469 ;
     RECT  16.776 49.427 18.705 49.469 ;
     RECT  21.132 49.343 22.014 49.469 ;
     RECT  22.86 49.427 26.805 49.469 ;
     RECT  31.104 49.343 32.526 49.469 ;
     RECT  34.272 49.427 37.674 49.469 ;
     RECT  41.04 49.427 43.362 49.469 ;
     RECT  44.1 49.379 44.802 49.469 ;
     RECT  45.612 49.379 47.502 49.469 ;
     RECT  29.052 49.307 30.078 49.475 ;
     RECT  45.615 49.469 46.35 49.475 ;
     RECT  3.492 49.469 5.994 49.505 ;
     RECT  6.732 49.469 6.822 49.505 ;
     RECT  7.815 49.469 9.306 49.505 ;
     RECT  10.515 49.469 11.574 49.505 ;
     RECT  16.884 49.469 17.694 49.505 ;
     RECT  20.376 49.343 20.394 49.505 ;
     RECT  21.204 49.469 21.69 49.505 ;
     RECT  23.22 49.469 24.534 49.505 ;
     RECT  25.272 49.469 25.47 49.505 ;
     RECT  34.272 49.469 37.605 49.505 ;
     RECT  41.04 49.469 41.814 49.505 ;
     RECT  42.66 49.469 43.005 49.505 ;
     RECT  44.1 49.469 44.37 49.505 ;
     RECT  47.376 49.469 47.394 49.505 ;
     RECT  23.436 49.505 24.498 49.517 ;
     RECT  34.272 49.505 36.162 49.517 ;
     RECT  41.04 49.505 41.67 49.517 ;
     RECT  4.032 49.505 4.05 49.541 ;
     RECT  5.04 49.505 5.274 49.541 ;
     RECT  6.732 49.505 6.75 49.541 ;
     RECT  8.748 49.505 8.766 49.541 ;
     RECT  17.424 49.505 17.442 49.541 ;
     RECT  21.204 49.505 21.405 49.541 ;
     RECT  25.452 49.505 25.47 49.541 ;
     RECT  29.415 49.475 30.078 49.541 ;
     RECT  31.104 49.469 31.122 49.541 ;
     RECT  34.815 49.517 36.162 49.541 ;
     RECT  36.936 49.505 37.605 49.541 ;
     RECT  41.652 49.517 41.67 49.541 ;
     RECT  44.1 49.505 44.118 49.541 ;
     RECT  5.115 49.541 5.274 49.577 ;
     RECT  23.58 49.517 24.105 49.577 ;
     RECT  11.556 49.505 11.574 49.649 ;
     RECT  2.415 49.469 2.505 49.697 ;
     RECT  5.115 49.577 5.205 49.697 ;
     RECT  7.815 49.505 7.905 49.697 ;
     RECT  10.515 49.505 10.605 49.697 ;
     RECT  13.215 49.469 14.454 49.697 ;
     RECT  15.264 49.469 16.005 49.697 ;
     RECT  18.615 49.469 18.705 49.697 ;
     RECT  21.315 49.541 21.405 49.697 ;
     RECT  24.015 49.577 24.105 49.697 ;
     RECT  26.715 49.469 26.805 49.697 ;
     RECT  29.415 49.541 29.505 49.697 ;
     RECT  32.115 49.469 32.205 49.697 ;
     RECT  34.815 49.541 34.905 49.697 ;
     RECT  37.515 49.541 37.605 49.697 ;
     RECT  40.215 49.427 40.305 49.697 ;
     RECT  42.915 49.505 43.005 49.697 ;
     RECT  45.615 49.475 45.705 49.697 ;
     RECT  48.315 49.427 48.405 49.697 ;
     RECT  13.932 49.697 14.454 50.791 ;
     RECT  15.264 49.697 15.282 50.855 ;
     RECT  13.932 50.791 14.526 51.547 ;
     RECT  13.86 51.547 14.526 51.691 ;
     RECT  13.788 51.691 14.526 51.821 ;
    LAYER M4 ;
     RECT  0.06 25.776 0.137 31.848 ;
     RECT  0.06 13.488 2.408 16.488 ;
     RECT  2.365 20.064 2.408 20.088 ;
     RECT  0.137 25.824 2.408 31.848 ;
     RECT  0.06 37.68 2.408 39.528 ;
     RECT  2.365 41.664 2.408 41.688 ;
     RECT  2.365 48.672 2.408 48.696 ;
     RECT  2.408 2.148 2.512 49.692 ;
     RECT  2.512 2.418 2.704 49.422 ;
     RECT  2.704 7.104 2.765 8.52 ;
     RECT  2.704 18.768 2.819 18.984 ;
     RECT  2.704 20.064 2.819 20.088 ;
     RECT  2.704 4.32 2.837 4.92 ;
     RECT  2.704 21.072 2.873 21.672 ;
     RECT  2.704 23.904 2.873 23.976 ;
     RECT  2.873 23.952 2.981 23.976 ;
     RECT  2.704 12.576 3.449 17.4 ;
     RECT  2.704 34.608 3.449 34.776 ;
     RECT  2.704 2.832 3.557 2.856 ;
     RECT  2.704 48.672 3.557 48.984 ;
     RECT  3.449 13.008 3.697 17.4 ;
     RECT  2.704 44.928 3.809 46.776 ;
     RECT  2.704 41.664 3.884 42.168 ;
     RECT  2.704 37.68 3.925 39.528 ;
     RECT  3.884 41.328 3.925 42.168 ;
     RECT  2.765 7.104 3.932 7.128 ;
     RECT  2.765 8.496 3.949 8.52 ;
     RECT  2.704 11.184 3.949 11.208 ;
     RECT  3.697 13.008 3.949 17.448 ;
     RECT  3.925 37.68 3.971 42.168 ;
     RECT  3.932 7.104 4.019 7.416 ;
     RECT  3.971 37.68 4.025 40.44 ;
     RECT  3.973 20.544 4.06 20.568 ;
     RECT  3.949 10.944 4.093 11.544 ;
     RECT  3.971 42.144 4.129 42.168 ;
     RECT  2.704 43.584 4.129 43.848 ;
     RECT  3.949 13.008 4.237 17.928 ;
     RECT  2.819 18.96 4.237 18.984 ;
     RECT  2.837 4.608 4.273 4.92 ;
     RECT  4.093 6.336 4.273 6.84 ;
     RECT  3.449 34.752 4.417 34.776 ;
     RECT  4.273 4.608 4.517 6.84 ;
     RECT  4.417 2.88 4.525 2.904 ;
     RECT  4.517 3.936 4.525 6.84 ;
     RECT  2.704 32.88 4.525 32.904 ;
     RECT  4.417 23.904 4.669 23.928 ;
     RECT  4.093 10.848 4.705 11.544 ;
     RECT  4.129 42.144 4.769 43.848 ;
     RECT  3.809 44.928 4.777 46.104 ;
     RECT  4.669 23.856 4.813 23.928 ;
     RECT  2.704 25.056 4.813 31.752 ;
     RECT  4.777 44.928 4.813 46.536 ;
     RECT  3.557 48.672 4.813 48.696 ;
     RECT  4.705 10.848 4.844 11.976 ;
     RECT  4.237 13.008 4.844 18.984 ;
     RECT  3.733 9.504 4.849 9.528 ;
     RECT  4.844 10.848 4.849 18.984 ;
     RECT  4.813 23.856 4.921 31.752 ;
     RECT  2.873 21.648 4.949 21.672 ;
     RECT  4.769 42.144 4.981 43.944 ;
     RECT  4.813 44.928 4.981 46.632 ;
     RECT  4.949 21.552 4.993 21.672 ;
     RECT  4.025 37.872 4.993 40.44 ;
     RECT  4.813 48.432 4.993 48.696 ;
     RECT  4.993 21.408 5.101 21.768 ;
     RECT  4.525 2.88 5.108 6.84 ;
     RECT  3.949 8.448 5.108 8.52 ;
     RECT  4.849 9.504 5.108 18.984 ;
     RECT  5.101 20.88 5.108 21.768 ;
     RECT  4.921 23.616 5.108 31.752 ;
     RECT  4.525 32.832 5.108 32.904 ;
     RECT  4.417 34.176 5.108 34.776 ;
     RECT  2.704 36.432 5.108 36.456 ;
     RECT  4.993 37.584 5.108 40.44 ;
     RECT  4.981 42.144 5.108 46.632 ;
     RECT  4.993 48.432 5.108 49.032 ;
     RECT  5.108 2.148 5.212 49.692 ;
     RECT  5.212 2.256 5.404 49.422 ;
     RECT  5.404 8.448 5.555 9.144 ;
     RECT  5.404 10.32 5.609 12.072 ;
     RECT  5.404 36.576 5.699 42.984 ;
     RECT  5.699 36.576 5.753 39.528 ;
     RECT  5.404 44.304 5.753 45.576 ;
     RECT  5.404 23.616 5.789 35.304 ;
     RECT  5.404 48.432 5.789 48.792 ;
     RECT  5.753 38.736 5.825 39.528 ;
     RECT  5.753 36.576 6.005 37.608 ;
     RECT  5.789 48.768 6.005 48.792 ;
     RECT  5.404 2.256 6.041 7.368 ;
     RECT  5.404 13.056 6.041 21.768 ;
     RECT  5.609 10.32 6.113 10.344 ;
     RECT  6.041 21.12 6.113 21.768 ;
     RECT  5.699 41.376 6.131 42.984 ;
     RECT  5.789 23.616 6.293 34.248 ;
     RECT  5.404 46.608 6.293 46.632 ;
     RECT  5.555 8.736 6.329 9.096 ;
     RECT  6.131 41.376 6.329 42.504 ;
     RECT  6.041 13.056 6.419 19.992 ;
     RECT  6.041 2.832 6.421 7.368 ;
     RECT  6.421 2.832 6.467 7.464 ;
     RECT  6.419 13.056 6.473 19.944 ;
     RECT  6.467 2.832 6.508 6.12 ;
     RECT  5.609 11.52 6.685 12.072 ;
     RECT  6.473 13.056 6.685 19.608 ;
     RECT  5.825 38.736 6.721 39.24 ;
     RECT  6.005 36.576 6.757 36.936 ;
     RECT  6.293 24.336 6.853 34.248 ;
     RECT  5.789 35.28 6.853 35.304 ;
     RECT  6.685 11.52 6.865 19.608 ;
     RECT  6.757 36.528 6.973 36.936 ;
     RECT  6.721 37.968 6.973 39.24 ;
     RECT  6.865 10.944 7.081 19.608 ;
     RECT  6.973 36.528 7.189 39.24 ;
     RECT  7.189 36.528 7.297 39.336 ;
     RECT  5.753 44.496 7.297 45.24 ;
     RECT  6.329 41.616 7.429 42.504 ;
     RECT  7.297 43.632 7.429 45.24 ;
     RECT  6.508 6.048 7.477 6.12 ;
     RECT  6.467 7.104 7.477 7.464 ;
     RECT  7.429 41.616 7.541 45.24 ;
     RECT  6.853 24.336 7.549 35.304 ;
     RECT  6.937 47.328 7.549 47.352 ;
     RECT  7.541 41.616 7.58 45.624 ;
     RECT  7.549 47.328 7.621 48.312 ;
     RECT  7.621 47.328 7.669 49.224 ;
     RECT  6.113 21.12 7.801 21.432 ;
     RECT  6.508 2.832 7.808 4.776 ;
     RECT  7.477 6.048 7.808 7.464 ;
     RECT  6.329 8.736 7.808 9.048 ;
     RECT  7.081 10.08 7.808 19.608 ;
     RECT  7.801 21.12 7.808 21.48 ;
     RECT  7.477 23.328 7.808 23.352 ;
     RECT  7.549 24.336 7.808 35.448 ;
     RECT  7.297 36.48 7.808 39.864 ;
     RECT  7.58 41.616 7.808 45.768 ;
     RECT  7.669 46.752 7.808 49.224 ;
     RECT  7.808 2.148 7.912 49.692 ;
     RECT  7.912 2.256 8.104 49.464 ;
     RECT  8.104 44.928 8.165 45.768 ;
     RECT  8.104 34.128 8.243 35.448 ;
     RECT  8.104 24.528 8.381 32.472 ;
     RECT  8.104 49.2 8.489 49.464 ;
     RECT  8.104 36.528 8.525 42.504 ;
     RECT  8.104 19.248 8.531 22.248 ;
     RECT  8.489 49.344 8.597 49.464 ;
     RECT  8.104 10.8 8.633 17.688 ;
     RECT  8.165 45.216 8.633 45.768 ;
     RECT  8.381 28.512 8.741 32.472 ;
     RECT  8.597 49.344 8.777 49.368 ;
     RECT  8.633 10.8 8.921 14.232 ;
     RECT  8.104 46.896 8.921 47.064 ;
     RECT  8.741 29.616 9.097 32.472 ;
     RECT  8.525 36.528 9.349 41.064 ;
     RECT  8.531 19.248 9.385 21.528 ;
     RECT  9.349 36.48 9.397 41.064 ;
     RECT  8.104 2.256 9.461 4.248 ;
     RECT  9.397 35.856 9.484 41.064 ;
     RECT  8.525 42.192 9.529 42.504 ;
     RECT  8.104 43.536 9.529 43.56 ;
     RECT  8.381 24.528 9.596 27.384 ;
     RECT  8.741 28.512 9.596 28.536 ;
     RECT  8.633 15.264 9.745 17.688 ;
     RECT  9.385 19.104 9.745 21.528 ;
     RECT  8.921 11.376 9.853 14.232 ;
     RECT  9.745 15.264 9.853 21.528 ;
     RECT  9.484 36.336 9.925 41.064 ;
     RECT  9.529 42.192 9.925 43.56 ;
     RECT  9.925 36.336 10.021 43.56 ;
     RECT  9.596 24.528 10.069 28.536 ;
     RECT  9.461 2.352 10.105 4.248 ;
     RECT  10.069 23.376 10.141 28.536 ;
     RECT  9.097 29.616 10.141 32.808 ;
     RECT  10.105 2.352 10.321 4.68 ;
     RECT  8.104 5.712 10.321 9.768 ;
     RECT  9.889 48.528 10.393 48.552 ;
     RECT  10.141 23.376 10.429 32.808 ;
     RECT  8.243 34.128 10.429 34.776 ;
     RECT  10.321 2.352 10.508 9.768 ;
     RECT  9.853 11.376 10.508 21.528 ;
     RECT  10.429 23.376 10.508 34.776 ;
     RECT  10.021 36.336 10.508 44.136 ;
     RECT  8.633 45.312 10.508 45.768 ;
     RECT  8.921 47.04 10.508 47.064 ;
     RECT  10.393 48.24 10.508 48.552 ;
     RECT  10.508 2.148 10.612 49.692 ;
     RECT  10.612 2.418 10.804 49.422 ;
     RECT  10.804 48.24 11.045 49.032 ;
     RECT  10.804 12.48 11.153 19.032 ;
     RECT  10.804 37.584 11.153 42.168 ;
     RECT  11.153 37.584 11.297 39.816 ;
     RECT  10.804 34.656 11.411 36.312 ;
     RECT  10.804 3.936 11.441 10.824 ;
     RECT  11.441 5.136 11.477 10.824 ;
     RECT  11.297 37.632 11.477 39.816 ;
     RECT  10.804 23.328 11.513 33.528 ;
     RECT  10.804 20.592 11.765 22.104 ;
     RECT  11.441 3.936 11.833 4.008 ;
     RECT  11.477 9.744 11.869 10.824 ;
     RECT  10.804 43.296 11.9 47.064 ;
     RECT  11.513 24.624 11.945 33.528 ;
     RECT  11.765 20.592 11.989 21.816 ;
     RECT  11.833 3.408 12.013 4.008 ;
     RECT  11.411 34.656 12.013 34.776 ;
     RECT  11.153 40.944 12.017 42.168 ;
     RECT  12.013 2.976 12.021 4.008 ;
     RECT  11.153 19.008 12.035 19.032 ;
     RECT  11.989 20.016 12.076 21.816 ;
     RECT  11.477 5.136 12.197 8.76 ;
     RECT  11.869 9.744 12.229 11.256 ;
     RECT  11.153 12.48 12.229 17.88 ;
     RECT  11.9 43.248 12.233 47.064 ;
     RECT  11.045 49.008 12.265 49.032 ;
     RECT  12.017 41.424 12.481 42.168 ;
     RECT  12.233 43.248 12.481 43.944 ;
     RECT  12.021 2.352 12.517 4.008 ;
     RECT  11.411 35.904 12.517 36.312 ;
     RECT  12.265 49.008 12.517 49.08 ;
     RECT  12.233 45.024 12.613 47.064 ;
     RECT  12.517 48.816 12.661 49.08 ;
     RECT  12.197 5.568 12.769 8.76 ;
     RECT  12.229 9.744 12.769 17.88 ;
     RECT  12.076 20.592 12.841 21.816 ;
     RECT  12.769 5.568 12.877 17.88 ;
     RECT  12.877 5.568 12.913 18.024 ;
     RECT  11.945 24.624 12.985 32.904 ;
     RECT  12.013 34.368 12.985 34.776 ;
     RECT  11.513 23.328 13.057 23.352 ;
     RECT  12.985 24.624 13.057 34.776 ;
     RECT  12.913 5.568 13.093 18.504 ;
     RECT  12.625 19.536 13.093 19.56 ;
     RECT  12.841 20.592 13.093 21.96 ;
     RECT  13.057 23.328 13.093 34.776 ;
     RECT  12.481 41.424 13.129 43.944 ;
     RECT  11.477 37.632 13.165 39.768 ;
     RECT  13.129 41.136 13.165 43.944 ;
     RECT  12.517 2.352 13.208 4.488 ;
     RECT  13.093 5.568 13.208 19.56 ;
     RECT  13.093 20.592 13.208 34.776 ;
     RECT  12.517 35.808 13.208 36.312 ;
     RECT  13.165 37.632 13.208 43.944 ;
     RECT  12.613 45.024 13.208 47.304 ;
     RECT  12.661 48.528 13.208 49.08 ;
     RECT  13.208 2.148 13.312 49.692 ;
     RECT  13.312 2.352 13.457 49.422 ;
     RECT  13.457 2.418 13.504 49.422 ;
     RECT  13.504 20.544 13.619 23.304 ;
     RECT  13.504 24.336 13.637 34.776 ;
     RECT  13.504 4.464 13.709 6.12 ;
     RECT  13.619 21.744 13.709 23.304 ;
     RECT  13.709 4.464 13.817 5.304 ;
     RECT  13.777 51.696 13.849 51.72 ;
     RECT  13.637 24.336 13.853 33.576 ;
     RECT  13.504 11.952 13.961 19.56 ;
     RECT  13.504 37.152 13.997 49.08 ;
     RECT  13.997 37.152 14.033 43.128 ;
     RECT  13.853 24.624 14.105 33.576 ;
     RECT  13.997 44.352 14.105 49.08 ;
     RECT  14.105 45.984 14.285 49.08 ;
     RECT  14.105 44.352 14.465 44.568 ;
     RECT  13.637 34.704 14.497 34.776 ;
     RECT  13.961 11.952 14.537 16.584 ;
     RECT  13.961 17.616 14.537 19.56 ;
     RECT  13.504 8.832 14.569 10.728 ;
     RECT  13.504 7.2 14.605 7.224 ;
     RECT  14.569 8.832 14.645 10.92 ;
     RECT  14.605 7.2 14.689 7.416 ;
     RECT  14.537 17.664 14.753 19.56 ;
     RECT  13.619 20.544 14.785 20.712 ;
     RECT  13.709 21.792 14.876 23.304 ;
     RECT  14.105 24.624 14.876 32.904 ;
     RECT  13.817 4.944 14.933 5.304 ;
     RECT  14.876 21.792 15.289 32.904 ;
     RECT  14.497 34.704 15.289 35.448 ;
     RECT  14.785 19.872 15.397 20.712 ;
     RECT  15.289 21.792 15.397 33.624 ;
     RECT  14.645 9.072 15.433 10.92 ;
     RECT  14.537 11.952 15.433 12.072 ;
     RECT  14.285 45.984 15.577 48.024 ;
     RECT  14.285 49.056 15.577 49.08 ;
     RECT  15.433 9.072 15.637 12.072 ;
     RECT  14.537 13.056 15.637 16.584 ;
     RECT  15.637 9.072 15.793 16.584 ;
     RECT  14.753 17.664 15.793 18.744 ;
     RECT  14.465 44.352 15.793 44.376 ;
     RECT  15.577 45.984 15.793 49.08 ;
     RECT  14.689 7.2 15.865 7.224 ;
     RECT  14.033 37.392 15.865 43.128 ;
     RECT  15.253 2.784 15.908 2.808 ;
     RECT  14.933 5.04 15.908 5.304 ;
     RECT  15.865 7.2 15.908 7.944 ;
     RECT  15.793 9.072 15.908 18.744 ;
     RECT  15.397 19.872 15.908 33.672 ;
     RECT  15.289 34.704 15.908 36.024 ;
     RECT  15.865 37.392 15.908 43.32 ;
     RECT  15.793 44.352 15.908 49.08 ;
     RECT  15.908 2.148 16.012 49.692 ;
     RECT  16.012 2.418 16.204 49.422 ;
     RECT  16.204 2.784 16.301 2.904 ;
     RECT  13.849 51.552 16.403 51.72 ;
     RECT  16.204 4.272 16.481 4.776 ;
     RECT  16.204 6.288 16.481 16.152 ;
     RECT  16.204 17.136 16.553 18.744 ;
     RECT  16.204 19.872 16.589 34.728 ;
     RECT  16.204 35.952 16.697 47.688 ;
     RECT  16.204 48.768 16.697 48.792 ;
     RECT  16.589 20.016 16.805 24.792 ;
     RECT  16.589 25.776 16.877 33.144 ;
     RECT  16.481 4.272 16.931 4.536 ;
     RECT  16.481 6.288 16.957 7.176 ;
     RECT  16.481 8.448 17.057 16.152 ;
     RECT  17.057 9.648 17.075 16.152 ;
     RECT  16.877 29.328 17.129 33.144 ;
     RECT  16.697 36 17.129 47.688 ;
     RECT  16.805 20.016 17.201 21.192 ;
     RECT  17.129 36 17.201 44.376 ;
     RECT  17.075 9.888 17.237 16.152 ;
     RECT  16.877 26.064 17.345 28.2 ;
     RECT  17.129 29.328 17.345 32.952 ;
     RECT  17.345 26.064 17.381 26.904 ;
     RECT  17.237 12 17.417 16.152 ;
     RECT  17.417 16.032 17.516 16.152 ;
     RECT  16.553 17.136 17.516 18.264 ;
     RECT  16.931 4.512 17.593 4.536 ;
     RECT  16.301 2.88 17.605 2.904 ;
     RECT  17.516 16.032 17.701 18.264 ;
     RECT  17.345 29.328 17.845 32.904 ;
     RECT  17.201 20.016 17.881 21.144 ;
     RECT  16.957 6.864 18.061 7.176 ;
     RECT  17.057 8.448 18.061 8.472 ;
     RECT  16.805 22.56 18.169 24.696 ;
     RECT  17.381 26.064 18.169 26.664 ;
     RECT  17.129 45.552 18.205 47.688 ;
     RECT  17.237 9.888 18.277 10.968 ;
     RECT  17.417 12 18.277 15 ;
     RECT  18.277 9.888 18.385 15 ;
     RECT  17.701 16.032 18.385 18.792 ;
     RECT  17.593 4.512 18.457 4.728 ;
     RECT  18.169 22.56 18.457 26.664 ;
     RECT  17.345 28.032 18.457 28.2 ;
     RECT  17.845 29.232 18.457 32.904 ;
     RECT  18.457 22.56 18.529 28.2 ;
     RECT  18.457 29.232 18.529 33.096 ;
     RECT  16.589 34.32 18.529 34.728 ;
     RECT  17.201 36 18.529 36.024 ;
     RECT  18.385 9.888 18.565 18.792 ;
     RECT  17.881 19.968 18.565 21.144 ;
     RECT  17.605 2.256 18.608 2.904 ;
     RECT  18.457 4.512 18.608 5.064 ;
     RECT  18.061 6.864 18.608 8.472 ;
     RECT  18.565 9.888 18.608 21.144 ;
     RECT  18.529 22.56 18.608 33.096 ;
     RECT  18.529 34.32 18.608 36.024 ;
     RECT  17.201 37.056 18.608 44.376 ;
     RECT  18.205 45.552 18.608 48.408 ;
     RECT  18.608 2.148 18.712 49.692 ;
     RECT  18.712 2.418 18.904 49.422 ;
     RECT  18.904 42.912 18.965 49.224 ;
     RECT  18.904 4.512 19.037 5.064 ;
     RECT  18.904 21.552 19.043 35.928 ;
     RECT  19.037 4.512 19.073 4.728 ;
     RECT  19.043 25.728 19.145 35.928 ;
     RECT  18.965 48.24 19.145 49.224 ;
     RECT  18.965 42.912 19.217 47.16 ;
     RECT  19.217 44.304 19.253 47.16 ;
     RECT  19.145 25.776 19.361 35.928 ;
     RECT  18.904 36.912 19.397 41.928 ;
     RECT  19.145 48.384 19.397 49.224 ;
     RECT  19.217 42.912 19.505 43.32 ;
     RECT  19.043 21.552 19.613 24.696 ;
     RECT  19.361 34.656 19.721 35.928 ;
     RECT  19.253 44.304 19.757 46.872 ;
     RECT  19.505 43.152 19.852 43.32 ;
     RECT  18.904 2.418 19.861 2.52 ;
     RECT  18.904 6.144 19.865 18.168 ;
     RECT  19.397 48.96 19.865 49.224 ;
     RECT  19.865 6.288 19.957 18.168 ;
     RECT  18.904 19.584 19.957 19.608 ;
     RECT  19.957 19.584 20.003 19.8 ;
     RECT  19.613 21.552 20.197 21.576 ;
     RECT  20.197 21.12 20.284 21.576 ;
     RECT  19.613 22.56 20.401 24.696 ;
     RECT  19.361 25.776 20.401 33.576 ;
     RECT  19.397 36.912 20.437 41.256 ;
     RECT  19.852 43.296 20.495 43.32 ;
     RECT  19.757 44.304 20.495 46.488 ;
     RECT  20.401 22.56 20.545 33.576 ;
     RECT  19.721 34.656 20.545 35.88 ;
     RECT  19.073 4.512 20.684 4.536 ;
     RECT  19.861 2.304 20.689 2.52 ;
     RECT  20.684 4.08 20.725 4.536 ;
     RECT  20.003 19.776 20.725 19.8 ;
     RECT  20.545 22.56 20.797 35.88 ;
     RECT  20.437 36.912 20.797 41.544 ;
     RECT  20.495 43.296 20.905 46.488 ;
     RECT  19.865 49.056 21.041 49.224 ;
     RECT  19.957 6.288 21.061 18.6 ;
     RECT  21.041 49.008 21.085 49.224 ;
     RECT  21.061 6.096 21.157 18.6 ;
     RECT  20.689 2.304 21.308 2.568 ;
     RECT  20.725 4.08 21.308 5.112 ;
     RECT  21.157 6.096 21.308 18.792 ;
     RECT  20.725 19.776 21.308 20.088 ;
     RECT  20.284 21.456 21.308 21.576 ;
     RECT  20.797 22.56 21.308 41.544 ;
     RECT  20.905 42.768 21.308 46.488 ;
     RECT  20.437 47.664 21.308 47.688 ;
     RECT  21.085 49.008 21.308 49.272 ;
     RECT  21.308 2.148 21.412 49.692 ;
     RECT  21.412 2.418 21.604 49.422 ;
     RECT  21.604 21.456 21.629 23.592 ;
     RECT  21.604 42.768 21.827 45 ;
     RECT  21.604 2.496 21.989 2.76 ;
     RECT  21.604 3.84 21.989 4.488 ;
     RECT  21.604 19.248 21.989 20.328 ;
     RECT  21.604 46.176 21.989 49.272 ;
     RECT  21.827 42.768 22.169 44.904 ;
     RECT  21.989 3.84 22.211 4.392 ;
     RECT  21.604 25.68 22.241 41.112 ;
     RECT  22.241 35.232 22.421 41.112 ;
     RECT  16.403 51.696 22.595 51.72 ;
     RECT  22.421 36.768 22.645 41.112 ;
     RECT  22.645 36.768 22.777 41.64 ;
     RECT  21.989 46.176 22.885 49.08 ;
     RECT  21.989 19.584 22.961 20.328 ;
     RECT  21.604 6.096 22.979 18.264 ;
     RECT  21.604 24.672 22.988 24.696 ;
     RECT  22.241 25.68 22.988 33.96 ;
     RECT  22.979 12.768 23.029 18.264 ;
     RECT  22.961 19.584 23.029 19.896 ;
     RECT  22.979 6.096 23.033 11.784 ;
     RECT  21.989 2.544 23.101 2.76 ;
     RECT  21.629 21.504 23.173 23.592 ;
     RECT  22.988 24.672 23.245 33.96 ;
     RECT  22.421 35.232 23.245 35.736 ;
     RECT  22.211 4.368 23.279 4.392 ;
     RECT  22.169 43.728 23.345 44.904 ;
     RECT  22.885 45.888 23.345 49.08 ;
     RECT  23.101 2.544 23.425 2.808 ;
     RECT  23.279 3.936 23.425 4.392 ;
     RECT  23.345 43.728 23.425 49.08 ;
     RECT  23.245 24.672 23.605 35.736 ;
     RECT  22.777 36.768 23.605 42.312 ;
     RECT  23.605 24.672 23.641 42.312 ;
     RECT  23.425 43.728 23.641 49.512 ;
     RECT  23.425 2.544 24.008 4.392 ;
     RECT  23.033 6.816 24.008 11.784 ;
     RECT  23.029 12.768 24.008 19.896 ;
     RECT  23.173 21.504 24.008 23.688 ;
     RECT  23.641 24.672 24.008 49.512 ;
     RECT  24.008 2.148 24.112 49.692 ;
     RECT  24.112 2.418 24.304 49.512 ;
     RECT  24.304 6.816 24.509 11.784 ;
     RECT  24.304 49.488 24.509 49.512 ;
     RECT  24.304 17.136 24.841 19.992 ;
     RECT  24.304 25.68 24.905 48.312 ;
     RECT  24.905 46.272 24.941 48.312 ;
     RECT  24.304 20.976 24.947 24.696 ;
     RECT  24.509 6.912 25.085 11.784 ;
     RECT  25.085 10.08 25.121 11.784 ;
     RECT  25.121 11.664 25.193 11.784 ;
     RECT  24.304 5.712 25.235 5.736 ;
     RECT  24.905 25.68 25.235 45.192 ;
     RECT  24.304 12.768 25.285 16.152 ;
     RECT  24.841 17.136 25.285 18.696 ;
     RECT  24.304 2.784 25.333 4.728 ;
     RECT  25.285 12.768 25.372 18.696 ;
     RECT  25.235 25.68 25.409 37.08 ;
     RECT  24.941 46.704 25.441 48.312 ;
     RECT  25.085 6.912 25.487 9 ;
     RECT  25.235 38.16 25.517 45.192 ;
     RECT  25.441 46.704 25.553 48.36 ;
     RECT  24.947 23.136 25.693 24.696 ;
     RECT  25.409 25.68 25.693 33.624 ;
     RECT  25.517 39.792 25.715 45.192 ;
     RECT  25.372 12.768 25.733 16.152 ;
     RECT  25.333 2.784 25.861 5.064 ;
     RECT  25.487 6.672 26.125 9 ;
     RECT  25.121 10.08 26.125 10.68 ;
     RECT  25.193 11.664 26.125 11.688 ;
     RECT  25.372 17.136 26.125 18.696 ;
     RECT  24.947 20.976 26.125 22.056 ;
     RECT  25.693 23.136 26.125 33.624 ;
     RECT  25.553 46.704 26.149 48.312 ;
     RECT  25.733 14.256 26.341 16.152 ;
     RECT  26.125 17.136 26.341 18.792 ;
     RECT  26.149 46.224 26.629 48.312 ;
     RECT  25.861 2.256 26.708 5.064 ;
     RECT  26.125 6.672 26.708 9.048 ;
     RECT  26.125 10.08 26.708 11.688 ;
     RECT  25.733 12.768 26.708 13.128 ;
     RECT  26.341 14.256 26.708 18.792 ;
     RECT  24.841 19.824 26.708 19.992 ;
     RECT  26.125 20.976 26.708 33.624 ;
     RECT  25.409 34.752 26.708 37.08 ;
     RECT  25.517 38.16 26.708 38.76 ;
     RECT  25.715 39.792 26.708 45 ;
     RECT  26.629 46.224 26.708 48.456 ;
     RECT  26.708 2.148 26.812 49.692 ;
     RECT  26.812 2.418 27.004 49.422 ;
     RECT  27.004 20.976 27.065 35.736 ;
     RECT  27.004 38.688 27.101 46.344 ;
     RECT  27.004 16.08 27.245 19.896 ;
     RECT  27.065 20.976 27.353 24.6 ;
     RECT  27.004 3.936 27.425 4.776 ;
     RECT  27.004 47.376 27.569 48.456 ;
     RECT  27.245 16.08 27.641 19.848 ;
     RECT  27.101 45.552 27.677 46.344 ;
     RECT  27.677 45.552 27.929 45.768 ;
     RECT  27.425 3.984 27.965 4.776 ;
     RECT  27.101 38.688 28.019 44.472 ;
     RECT  27.004 2.688 28.037 2.856 ;
     RECT  27.004 5.856 28.067 10.2 ;
     RECT  28.067 5.856 28.145 7.992 ;
     RECT  27.004 37.44 28.165 37.464 ;
     RECT  28.037 2.688 28.181 2.808 ;
     RECT  27.353 21.648 28.181 24.6 ;
     RECT  28.165 37.008 28.252 37.464 ;
     RECT  27.569 47.376 28.357 48.168 ;
     RECT  27.065 25.584 28.537 35.736 ;
     RECT  27.004 11.376 28.597 13.416 ;
     RECT  27.004 14.448 28.597 15 ;
     RECT  27.641 19.2 28.609 19.848 ;
     RECT  28.597 11.376 28.645 15 ;
     RECT  28.145 5.856 28.681 6.84 ;
     RECT  28.181 22.032 28.681 24.6 ;
     RECT  28.537 25.584 28.681 35.928 ;
     RECT  27.641 16.08 28.861 17.976 ;
     RECT  27.965 3.984 29.029 4.008 ;
     RECT  28.681 5.472 29.029 6.84 ;
     RECT  28.252 37.44 29.149 37.464 ;
     RECT  28.019 38.688 29.149 38.76 ;
     RECT  28.861 16.08 29.257 18.024 ;
     RECT  28.609 19.2 29.257 20.328 ;
     RECT  28.145 7.968 29.269 7.992 ;
     RECT  28.067 8.976 29.269 10.2 ;
     RECT  29.257 16.08 29.269 20.328 ;
     RECT  29.149 37.44 29.269 38.76 ;
     RECT  28.019 39.744 29.269 44.472 ;
     RECT  29.269 7.92 29.329 10.2 ;
     RECT  28.645 11.232 29.329 15 ;
     RECT  28.181 2.688 29.408 2.712 ;
     RECT  29.029 3.792 29.408 6.84 ;
     RECT  29.329 7.92 29.408 15 ;
     RECT  29.269 16.08 29.408 20.616 ;
     RECT  28.681 22.032 29.408 35.928 ;
     RECT  29.269 37.44 29.408 44.472 ;
     RECT  27.929 45.552 29.408 45.576 ;
     RECT  28.357 47.04 29.408 48.168 ;
     RECT  29.029 49.44 29.408 49.464 ;
     RECT  29.408 2.148 29.512 49.692 ;
     RECT  29.512 2.4 29.704 49.422 ;
     RECT  29.704 5.376 30.124 35.736 ;
     RECT  30.124 5.376 30.131 20.568 ;
     RECT  29.704 2.4 30.197 3.96 ;
     RECT  30.124 22.032 30.233 35.736 ;
     RECT  30.131 5.376 30.323 18.744 ;
     RECT  30.197 2.4 30.553 2.664 ;
     RECT  30.131 19.776 30.601 20.568 ;
     RECT  29.704 45.552 30.629 45.576 ;
     RECT  30.323 5.568 30.659 18.744 ;
     RECT  30.659 5.568 30.701 10.152 ;
     RECT  29.704 39.744 30.764 39.768 ;
     RECT  29.704 40.896 30.764 41.976 ;
     RECT  30.764 39.744 30.769 41.976 ;
     RECT  29.704 43.008 30.769 43.128 ;
     RECT  30.701 5.568 30.773 9.768 ;
     RECT  30.233 23.664 30.773 35.736 ;
     RECT  29.704 37.824 30.805 38.76 ;
     RECT  30.769 39.744 30.805 43.128 ;
     RECT  30.805 37.824 30.851 43.128 ;
     RECT  30.773 5.568 30.917 9.672 ;
     RECT  30.851 37.824 30.949 39.336 ;
     RECT  30.197 3.936 30.985 3.96 ;
     RECT  30.917 7.92 31.061 9.672 ;
     RECT  30.917 5.568 31.091 6.888 ;
     RECT  30.851 40.896 31.093 43.128 ;
     RECT  29.704 44.16 31.093 44.472 ;
     RECT  29.704 47.712 31.093 48.984 ;
     RECT  30.659 11.136 31.097 18.744 ;
     RECT  30.773 25.296 31.133 35.736 ;
     RECT  30.233 22.032 31.237 22.632 ;
     RECT  31.091 5.568 31.285 6.792 ;
     RECT  31.093 40.896 31.285 44.472 ;
     RECT  31.097 16.032 31.333 18.744 ;
     RECT  30.601 19.776 31.333 20.184 ;
     RECT  31.093 46.752 31.381 48.984 ;
     RECT  31.133 29.28 31.532 35.736 ;
     RECT  31.381 46.08 31.561 48.984 ;
     RECT  31.237 21.648 31.669 22.632 ;
     RECT  30.773 23.664 31.669 24.168 ;
     RECT  31.333 16.032 31.957 20.184 ;
     RECT  31.285 40.896 31.993 44.52 ;
     RECT  30.553 2.304 32.065 2.664 ;
     RECT  30.985 3.936 32.065 4.296 ;
     RECT  32.065 2.304 32.108 4.296 ;
     RECT  31.285 5.376 32.108 6.792 ;
     RECT  31.061 7.92 32.108 9.48 ;
     RECT  31.097 11.136 32.108 15 ;
     RECT  31.957 16.032 32.108 20.376 ;
     RECT  31.669 21.648 32.108 24.168 ;
     RECT  31.133 25.296 32.108 28.2 ;
     RECT  31.532 29.28 32.108 36.024 ;
     RECT  30.949 37.008 32.108 39.336 ;
     RECT  31.993 40.56 32.108 44.52 ;
     RECT  31.561 46.08 32.108 49.032 ;
     RECT  32.108 2.148 32.212 49.692 ;
     RECT  32.212 2.418 32.404 49.422 ;
     RECT  32.404 35.712 32.465 44.472 ;
     RECT  32.404 2.544 32.537 3.864 ;
     RECT  32.404 45.696 32.645 49.032 ;
     RECT  32.537 3.36 32.681 3.864 ;
     RECT  32.465 35.712 32.723 38.808 ;
     RECT  32.723 37.68 32.764 38.808 ;
     RECT  32.645 45.696 32.825 48.984 ;
     RECT  32.404 20.112 33.041 22.248 ;
     RECT  32.465 39.888 33.059 44.472 ;
     RECT  32.404 23.328 33.077 24.168 ;
     RECT  32.404 29.28 33.077 34.392 ;
     RECT  32.825 46.08 33.107 48.984 ;
     RECT  33.041 20.304 33.113 22.248 ;
     RECT  32.404 25.2 33.149 28.296 ;
     RECT  33.149 25.824 33.257 28.296 ;
     RECT  33.077 23.376 33.329 24.168 ;
     RECT  33.107 46.752 33.329 48.984 ;
     RECT  33.329 23.664 33.397 24.168 ;
     RECT  32.681 3.84 33.469 3.864 ;
     RECT  32.404 11.28 33.469 13.032 ;
     RECT  32.404 14.112 33.469 15 ;
     RECT  32.404 5.568 33.509 9.624 ;
     RECT  33.059 40.32 33.509 44.472 ;
     RECT  33.509 40.32 33.545 43.128 ;
     RECT  33.329 46.752 33.581 46.776 ;
     RECT  32.404 16.032 33.613 18.984 ;
     RECT  32.764 37.68 33.617 38.472 ;
     RECT  33.469 11.28 33.653 15 ;
     RECT  33.509 44.112 33.653 44.472 ;
     RECT  33.113 20.304 33.779 22.056 ;
     RECT  33.617 38.448 33.793 38.472 ;
     RECT  33.653 44.4 33.797 44.472 ;
     RECT  33.469 3.84 33.829 4.488 ;
     RECT  32.723 35.712 33.829 36.456 ;
     RECT  33.077 33.552 33.937 34.392 ;
     RECT  33.257 26.112 34.117 28.296 ;
     RECT  33.077 29.28 34.117 32.568 ;
     RECT  33.653 11.664 34.261 15 ;
     RECT  33.613 16.032 34.261 19.032 ;
     RECT  33.329 47.808 34.261 48.984 ;
     RECT  33.509 6.24 34.268 9.624 ;
     RECT  34.117 26.112 34.333 32.568 ;
     RECT  33.937 33.552 34.333 34.536 ;
     RECT  34.333 26.112 34.369 34.536 ;
     RECT  34.261 47.808 34.369 49.512 ;
     RECT  34.268 6.24 34.513 10.536 ;
     RECT  33.397 23.664 34.513 24.744 ;
     RECT  34.369 26.112 34.513 34.728 ;
     RECT  33.797 44.448 34.549 44.472 ;
     RECT  34.261 11.664 34.652 19.272 ;
     RECT  33.779 20.304 34.652 20.904 ;
     RECT  34.513 5.568 34.693 10.536 ;
     RECT  34.652 11.664 34.693 20.904 ;
     RECT  33.545 40.944 34.765 43.128 ;
     RECT  34.549 44.448 34.765 45 ;
     RECT  33.829 2.88 34.808 4.488 ;
     RECT  34.693 5.568 34.808 20.904 ;
     RECT  33.779 22.032 34.808 22.056 ;
     RECT  34.513 23.664 34.808 34.728 ;
     RECT  33.829 35.712 34.808 37.128 ;
     RECT  33.793 38.448 34.808 38.712 ;
     RECT  34.765 40.944 34.808 45.096 ;
     RECT  34.369 47.664 34.808 49.512 ;
     RECT  34.808 2.148 34.912 49.692 ;
     RECT  34.912 2.256 35.104 49.512 ;
     RECT  35.104 38.448 35.219 38.808 ;
     RECT  35.104 10.896 35.363 20.712 ;
     RECT  35.104 46.8 35.363 49.512 ;
     RECT  35.104 2.256 35.381 9.624 ;
     RECT  35.381 2.256 35.411 9 ;
     RECT  35.411 2.256 35.452 2.28 ;
     RECT  35.363 10.896 35.453 13.656 ;
     RECT  35.453 10.896 35.489 11.928 ;
     RECT  35.104 26.112 35.507 37.224 ;
     RECT  35.219 38.544 35.507 38.808 ;
     RECT  35.411 3.696 35.633 9 ;
     RECT  35.633 5.472 35.705 9 ;
     RECT  35.363 14.976 35.741 20.712 ;
     RECT  35.104 22.032 35.849 24.792 ;
     RECT  35.507 26.112 35.857 37.128 ;
     RECT  35.857 26.112 35.885 35.928 ;
     RECT  35.885 34.944 35.891 35.928 ;
     RECT  35.885 26.112 35.939 33.864 ;
     RECT  35.705 8.448 35.957 9 ;
     RECT  35.507 38.784 35.957 38.808 ;
     RECT  35.939 26.112 36.137 33.672 ;
     RECT  36.137 33.648 36.227 33.672 ;
     RECT  35.104 41.904 36.277 45 ;
     RECT  35.741 14.976 36.353 19.32 ;
     RECT  36.353 14.976 36.371 19.272 ;
     RECT  35.741 20.4 36.421 20.712 ;
     RECT  35.104 40.272 36.421 40.584 ;
     RECT  36.277 41.568 36.421 45 ;
     RECT  35.849 22.032 36.425 24.744 ;
     RECT  35.363 46.944 36.425 49.512 ;
     RECT  36.425 48.864 36.461 49.512 ;
     RECT  35.957 8.544 36.565 9 ;
     RECT  35.633 3.696 36.668 4.488 ;
     RECT  35.705 5.472 36.668 6.84 ;
     RECT  36.565 8.544 36.673 9.096 ;
     RECT  36.425 46.944 36.745 47.736 ;
     RECT  36.673 8.544 36.817 9.912 ;
     RECT  36.668 3.696 36.853 6.84 ;
     RECT  36.421 40.272 36.925 45 ;
     RECT  36.745 46.176 36.925 47.736 ;
     RECT  36.925 40.272 36.989 47.736 ;
     RECT  35.891 34.944 36.997 35.832 ;
     RECT  35.857 36.912 36.997 37.128 ;
     RECT  36.997 34.944 37.033 37.128 ;
     RECT  37.033 34.944 37.069 37.464 ;
     RECT  36.817 8.544 37.141 10.2 ;
     RECT  35.489 11.376 37.141 11.928 ;
     RECT  37.141 8.544 37.148 11.928 ;
     RECT  35.453 13.632 37.177 13.656 ;
     RECT  37.069 34.944 37.321 37.656 ;
     RECT  36.371 18.528 37.349 19.272 ;
     RECT  36.853 3.408 37.393 7.464 ;
     RECT  37.148 8.544 37.393 12.264 ;
     RECT  36.461 49.056 37.501 49.512 ;
     RECT  37.393 3.408 37.508 12.264 ;
     RECT  37.177 13.632 37.508 13.704 ;
     RECT  36.371 14.976 37.508 17.208 ;
     RECT  37.349 18.528 37.508 19.416 ;
     RECT  36.421 20.4 37.508 21 ;
     RECT  36.425 22.464 37.508 24.744 ;
     RECT  36.137 26.112 37.508 32.568 ;
     RECT  37.321 34.944 37.508 38.424 ;
     RECT  36.989 39.888 37.508 47.736 ;
     RECT  37.501 48.96 37.508 49.512 ;
     RECT  37.508 2.148 37.612 49.692 ;
     RECT  37.612 2.418 37.804 49.512 ;
     RECT  37.804 8.832 37.865 9.624 ;
     RECT  37.804 20.4 37.865 25.032 ;
     RECT  37.865 20.976 37.937 25.032 ;
     RECT  37.804 10.848 37.955 12.552 ;
     RECT  37.804 35.808 37.955 37.608 ;
     RECT  37.804 14.784 37.973 17.496 ;
     RECT  37.804 18.528 38.153 19.272 ;
     RECT  37.804 5.136 38.333 6.84 ;
     RECT  37.955 11.76 38.333 12.552 ;
     RECT  37.937 20.976 38.369 22.488 ;
     RECT  37.973 14.784 38.441 17.448 ;
     RECT  37.804 47.616 38.513 47.736 ;
     RECT  38.441 14.832 38.549 17.448 ;
     RECT  37.804 40.56 38.579 45.192 ;
     RECT  38.333 6.576 38.729 6.84 ;
     RECT  38.369 20.976 38.729 21 ;
     RECT  37.937 23.664 38.765 25.032 ;
     RECT  37.804 13.536 38.801 13.704 ;
     RECT  37.955 36.48 38.801 37.464 ;
     RECT  37.804 46.176 38.801 46.2 ;
     RECT  37.865 8.976 38.837 9.624 ;
     RECT  38.333 12.528 38.837 12.552 ;
     RECT  38.579 40.56 38.837 45 ;
     RECT  38.333 5.136 38.909 5.592 ;
     RECT  37.804 26.112 38.981 33.192 ;
     RECT  37.804 38.736 39.013 39.336 ;
     RECT  38.837 40.56 39.013 41.64 ;
     RECT  38.905 2.256 39.049 2.28 ;
     RECT  38.801 37.008 39.061 37.464 ;
     RECT  39.013 38.736 39.061 41.64 ;
     RECT  38.153 18.528 39.116 19.032 ;
     RECT  39.061 37.008 39.148 41.64 ;
     RECT  38.729 6.576 39.197 6.696 ;
     RECT  38.513 47.712 39.337 47.736 ;
     RECT  37.804 48.768 39.337 49.512 ;
     RECT  37.804 34.176 39.349 34.2 ;
     RECT  39.085 35.664 39.349 35.832 ;
     RECT  38.869 4.128 39.404 4.152 ;
     RECT  38.801 13.584 39.445 13.704 ;
     RECT  39.445 13.584 39.733 13.944 ;
     RECT  38.549 14.976 39.733 17.448 ;
     RECT  38.369 21.984 39.805 22.488 ;
     RECT  38.765 23.664 39.805 23.688 ;
     RECT  38.905 46.368 39.841 46.392 ;
     RECT  39.337 47.712 39.841 49.512 ;
     RECT  39.404 4.128 39.913 4.632 ;
     RECT  39.049 2.256 40.057 2.856 ;
     RECT  39.349 34.176 40.057 35.832 ;
     RECT  39.805 21.984 40.069 23.688 ;
     RECT  38.981 26.112 40.069 32.568 ;
     RECT  40.057 33.552 40.069 35.832 ;
     RECT  39.116 18.432 40.165 19.032 ;
     RECT  40.057 2.256 40.208 2.904 ;
     RECT  39.913 4.128 40.208 5.064 ;
     RECT  39.197 6.672 40.208 6.696 ;
     RECT  39.769 7.872 40.208 7.992 ;
     RECT  38.837 8.976 40.208 9 ;
     RECT  40.165 10.704 40.208 10.728 ;
     RECT  39.733 13.584 40.208 17.448 ;
     RECT  40.165 18.432 40.208 19.272 ;
     RECT  38.905 20.304 40.208 20.328 ;
     RECT  40.069 21.984 40.208 23.976 ;
     RECT  38.765 25.008 40.208 25.032 ;
     RECT  40.069 26.112 40.208 35.832 ;
     RECT  39.148 37.008 40.208 37.608 ;
     RECT  39.148 38.736 40.208 41.64 ;
     RECT  38.837 42.768 40.208 45 ;
     RECT  39.841 46.368 40.208 49.512 ;
     RECT  40.208 2.148 40.312 49.692 ;
     RECT  40.312 2.256 40.504 49.512 ;
     RECT  40.504 2.256 40.637 9.096 ;
     RECT  40.504 19.056 40.709 21.144 ;
     RECT  40.504 14.832 40.781 18.072 ;
     RECT  40.637 3.744 40.924 9.096 ;
     RECT  40.504 48.672 41.069 49.512 ;
     RECT  40.924 4.512 41.105 9.096 ;
     RECT  40.709 19.056 41.315 19.272 ;
     RECT  40.504 40.56 41.321 45.864 ;
     RECT  41.105 8.496 41.411 9.096 ;
     RECT  40.781 14.832 41.411 17.976 ;
     RECT  40.504 38.976 41.501 39.288 ;
     RECT  41.321 41.376 41.507 45.864 ;
     RECT  40.504 35.808 41.533 35.832 ;
     RECT  40.504 26.112 41.569 34.824 ;
     RECT  41.533 35.808 41.569 36.024 ;
     RECT  40.504 47.328 41.569 47.352 ;
     RECT  41.069 48.672 41.569 48.696 ;
     RECT  41.315 19.104 41.603 19.272 ;
     RECT  40.709 20.304 41.603 21.144 ;
     RECT  41.603 20.448 41.605 21.144 ;
     RECT  41.507 45.84 41.605 45.864 ;
     RECT  40.637 2.256 41.645 2.664 ;
     RECT  41.605 20.448 41.681 21.432 ;
     RECT  40.504 22.848 41.701 24.984 ;
     RECT  41.681 21.072 41.747 21.432 ;
     RECT  41.747 21.408 41.785 21.432 ;
     RECT  41.701 22.752 41.785 24.984 ;
     RECT  40.504 11.424 41.821 12.504 ;
     RECT  40.504 13.584 41.821 13.656 ;
     RECT  41.821 11.424 41.929 13.656 ;
     RECT  41.929 10.848 41.965 13.656 ;
     RECT  40.504 37.44 42.001 37.608 ;
     RECT  41.411 9.072 42.037 9.096 ;
     RECT  41.785 21.408 42.109 24.984 ;
     RECT  41.569 26.112 42.109 36.024 ;
     RECT  42.109 21.408 42.145 36.024 ;
     RECT  42.001 37.44 42.145 38.184 ;
     RECT  42.037 9.072 42.253 9.72 ;
     RECT  41.965 10.848 42.253 13.752 ;
     RECT  42.145 21.408 42.613 38.184 ;
     RECT  41.501 39.264 42.613 39.288 ;
     RECT  41.569 47.328 42.613 48.696 ;
     RECT  41.507 41.376 42.685 44.664 ;
     RECT  41.605 45.84 42.685 46.2 ;
     RECT  42.613 21.408 42.721 39.288 ;
     RECT  41.105 4.512 42.757 7.464 ;
     RECT  41.603 19.104 42.793 19.128 ;
     RECT  42.757 4.512 42.829 7.944 ;
     RECT  42.253 9.072 42.829 13.752 ;
     RECT  41.645 2.256 42.908 2.28 ;
     RECT  42.829 4.512 42.908 13.752 ;
     RECT  41.411 14.976 42.908 17.976 ;
     RECT  42.793 19.104 42.908 19.368 ;
     RECT  42.721 21.264 42.908 39.288 ;
     RECT  42.685 41.376 42.908 46.2 ;
     RECT  42.613 47.328 42.908 48.792 ;
     RECT  42.908 2.148 43.012 49.692 ;
     RECT  43.012 2.418 43.204 49.422 ;
     RECT  43.204 26.112 43.373 34.92 ;
     RECT  43.204 46.752 43.445 49.032 ;
     RECT  43.204 5.136 43.481 13.896 ;
     RECT  43.204 36.96 43.481 45.288 ;
     RECT  43.481 38.304 43.625 41.64 ;
     RECT  43.445 46.752 43.733 47.352 ;
     RECT  43.625 38.304 43.769 41.592 ;
     RECT  43.481 5.136 43.805 13.704 ;
     RECT  43.204 19.344 43.985 23.688 ;
     RECT  43.481 36.96 44.057 36.984 ;
     RECT  43.805 5.136 44.093 8.184 ;
     RECT  43.769 39.648 44.195 41.592 ;
     RECT  43.204 2.784 44.197 3.432 ;
     RECT  43.733 46.752 44.233 46.824 ;
     RECT  44.093 5.136 44.269 6.936 ;
     RECT  44.197 2.256 44.281 4.008 ;
     RECT  43.204 16.032 44.305 17.976 ;
     RECT  43.985 20.064 44.305 23.688 ;
     RECT  43.805 9.216 44.309 13.704 ;
     RECT  43.445 48.384 44.413 49.032 ;
     RECT  44.309 13.056 44.453 13.704 ;
     RECT  44.453 13.056 44.489 13.512 ;
     RECT  43.769 38.304 44.593 38.52 ;
     RECT  43.481 42.72 44.732 45.288 ;
     RECT  44.233 46.368 44.732 46.824 ;
     RECT  44.732 42.72 44.737 46.824 ;
     RECT  44.413 47.856 44.737 49.032 ;
     RECT  44.593 38.208 44.828 38.52 ;
     RECT  44.195 39.648 44.828 40.68 ;
     RECT  44.737 42.72 44.845 49.032 ;
     RECT  44.093 8.16 44.953 8.184 ;
     RECT  44.309 9.216 44.953 11.976 ;
     RECT  44.305 20.064 44.989 24.648 ;
     RECT  44.305 16.032 45.205 18.792 ;
     RECT  44.989 20.064 45.205 25.08 ;
     RECT  44.828 38.208 45.349 40.68 ;
     RECT  44.953 8.16 45.493 11.976 ;
     RECT  44.489 13.488 45.493 13.512 ;
     RECT  43.204 14.976 45.529 15 ;
     RECT  45.205 16.032 45.529 25.08 ;
     RECT  45.349 38.208 45.529 40.872 ;
     RECT  44.281 2.496 45.608 4.008 ;
     RECT  44.269 5.088 45.608 6.936 ;
     RECT  45.493 8.16 45.608 13.512 ;
     RECT  45.529 14.976 45.608 25.08 ;
     RECT  43.373 26.112 45.608 34.776 ;
     RECT  44.737 36.144 45.608 36.168 ;
     RECT  45.529 37.968 45.608 40.872 ;
     RECT  44.845 42 45.608 49.032 ;
     RECT  45.608 2.148 45.712 49.692 ;
     RECT  45.712 2.256 45.904 49.464 ;
     RECT  45.904 22.704 46.037 35.352 ;
     RECT  45.904 2.256 46.073 8.856 ;
     RECT  46.037 33.648 46.073 35.352 ;
     RECT  46.037 22.704 46.081 32.568 ;
     RECT  45.904 42.048 46.109 46.728 ;
     RECT  46.073 2.256 46.145 7.752 ;
     RECT  45.904 13.632 46.145 21.192 ;
     RECT  46.145 19.344 46.211 21.192 ;
     RECT  45.904 37.296 46.211 40.872 ;
     RECT  45.904 9.84 46.217 12.552 ;
     RECT  45.904 47.856 46.253 49.464 ;
     RECT  46.145 2.256 46.289 6.936 ;
     RECT  46.073 33.648 46.289 33.672 ;
     RECT  46.211 19.968 46.397 21.192 ;
     RECT  46.211 37.296 46.397 39.336 ;
     RECT  46.109 42.048 46.397 45.72 ;
     RECT  46.289 5.136 46.433 6.936 ;
     RECT  46.397 20.688 46.505 21.192 ;
     RECT  46.289 2.256 46.541 2.808 ;
     RECT  46.073 8.832 46.613 8.856 ;
     RECT  46.217 11.232 46.721 12.552 ;
     RECT  46.073 34.752 46.739 35.352 ;
     RECT  46.217 9.84 46.793 9.864 ;
     RECT  46.397 42.048 46.829 45.624 ;
     RECT  46.145 13.632 46.973 18.216 ;
     RECT  46.397 37.296 47.005 37.992 ;
     RECT  47.005 37.056 47.029 37.992 ;
     RECT  46.211 40.464 47.041 40.872 ;
     RECT  46.541 2.784 47.045 2.808 ;
     RECT  47.029 36.432 47.089 37.992 ;
     RECT  46.433 5.808 47.149 6.936 ;
     RECT  46.739 34.752 47.153 34.92 ;
     RECT  47.089 37.44 47.153 37.992 ;
     RECT  46.081 22.752 47.185 32.568 ;
     RECT  46.397 39.312 47.261 39.336 ;
     RECT  47.041 40.464 47.293 41.064 ;
     RECT  46.829 42.048 47.293 44.712 ;
     RECT  46.721 11.376 47.317 12.552 ;
     RECT  46.973 14.256 47.333 18.216 ;
     RECT  47.293 40.416 47.333 44.712 ;
     RECT  47.149 5.808 47.401 7.368 ;
     RECT  46.505 21.168 47.437 21.192 ;
     RECT  47.153 37.968 47.473 37.992 ;
     RECT  46.289 3.84 47.509 3.864 ;
     RECT  47.401 5.808 47.557 7.416 ;
     RECT  47.509 20.016 47.581 20.04 ;
     RECT  47.437 21.168 47.581 21.432 ;
     RECT  46.109 46.704 47.581 46.728 ;
     RECT  47.581 46.224 48.013 46.728 ;
     RECT  47.509 3.84 48.308 3.96 ;
     RECT  47.557 5.616 48.308 7.416 ;
     RECT  47.977 9.072 48.308 9.096 ;
     RECT  47.317 11.376 48.308 12.792 ;
     RECT  47.333 14.256 48.308 18.168 ;
     RECT  47.581 20.016 48.308 21.432 ;
     RECT  47.185 22.752 48.308 32.952 ;
     RECT  47.317 34.224 48.308 34.248 ;
     RECT  47.089 36.432 48.308 36.456 ;
     RECT  47.473 37.968 48.308 39.048 ;
     RECT  47.333 40.416 48.308 40.44 ;
     RECT  47.333 41.76 48.308 44.712 ;
     RECT  48.013 46.224 48.308 46.872 ;
     RECT  46.253 48.24 48.308 49.464 ;
     RECT  48.308 2.148 48.412 49.692 ;
     RECT  48.412 2.418 48.604 49.422 ;
     RECT  48.604 7.392 48.665 7.416 ;
     RECT  48.604 11.952 48.665 12.024 ;
     RECT  48.604 14.976 48.665 19.992 ;
     RECT  48.604 34.464 48.665 34.488 ;
     RECT  48.665 16.08 48.755 19.992 ;
     RECT  48.604 21.408 48.755 21.768 ;
     RECT  48.604 23.328 48.755 24.648 ;
     RECT  48.604 36.096 48.809 36.12 ;
     RECT  48.755 16.08 48.845 19.608 ;
     RECT  48.604 42.48 48.845 44.664 ;
     RECT  48.604 38.688 48.881 38.712 ;
     RECT  48.604 9.072 48.917 9.096 ;
     RECT  48.755 21.744 48.917 21.768 ;
     RECT  48.665 12 48.953 12.024 ;
     RECT  48.755 23.664 49.997 23.688 ;
     RECT  48.665 14.976 50.213 15 ;
     RECT  48.604 26.112 50.537 32.568 ;
     RECT  50.537 26.112 50.713 32.136 ;
     RECT  48.845 42.768 50.749 44.664 ;
     RECT  50.749 42.768 51.731 44.808 ;
     RECT  48.845 16.08 51.804 19.08 ;
     RECT  50.713 26.064 51.804 32.136 ;
     RECT  51.731 42.96 51.804 44.808 ;
    LAYER M5 ;
     RECT  2.4 2.137 2.52 2.151 ;
     RECT  5.1 2.137 5.22 2.151 ;
     RECT  7.8 2.137 7.92 2.151 ;
     RECT  10.5 2.137 10.62 2.151 ;
     RECT  13.2 2.137 13.32 2.151 ;
     RECT  15.9 2.137 16.02 2.151 ;
     RECT  18.6 2.137 18.72 2.151 ;
     RECT  21.3 2.137 21.42 2.151 ;
     RECT  24 2.137 24.12 2.151 ;
     RECT  26.7 2.137 26.82 2.151 ;
     RECT  29.4 2.137 29.52 2.151 ;
     RECT  32.1 2.137 32.22 2.151 ;
     RECT  34.8 2.137 34.92 2.151 ;
     RECT  37.5 2.137 37.62 2.151 ;
     RECT  40.2 2.137 40.32 2.151 ;
     RECT  42.9 2.137 43.02 2.151 ;
     RECT  45.6 2.137 45.72 2.151 ;
     RECT  48.3 2.137 48.42 2.151 ;
     RECT  5.1 2.151 5.412 2.245 ;
     RECT  18.6 2.151 18.912 2.245 ;
     RECT  26.7 2.151 27.012 2.245 ;
     RECT  34.8 2.151 35.112 2.245 ;
     RECT  45.6 2.151 45.912 2.245 ;
     RECT  10.5 2.151 10.812 2.341 ;
     RECT  21.3 2.151 21.612 2.485 ;
     RECT  29.4 2.151 29.712 2.533 ;
     RECT  29.4 2.533 29.928 2.677 ;
     RECT  24 2.151 24.312 2.773 ;
     RECT  2.4 2.151 2.712 2.821 ;
     RECT  34.8 2.245 35.4 2.869 ;
     RECT  17.616 2.245 18.912 2.915 ;
     RECT  33.84 2.869 35.4 2.915 ;
     RECT  29.04 2.677 29.928 3.299 ;
     RECT  12.048 2.341 12.072 3.443 ;
     RECT  5.1 2.245 5.88 3.539 ;
     RECT  45.6 2.245 46.2 3.539 ;
     RECT  7.8 2.151 8.112 3.685 ;
     RECT  40.2 2.151 40.512 3.733 ;
     RECT  20.736 2.485 21.612 3.829 ;
     RECT  33.84 2.915 35.352 3.875 ;
     RECT  5.1 3.539 5.412 3.925 ;
     RECT  23.328 2.773 24.312 3.925 ;
     RECT  25.872 2.245 27.012 3.925 ;
     RECT  32.1 2.151 32.412 3.925 ;
     RECT  23.328 3.925 27.012 3.971 ;
     RECT  24 3.971 27.012 4.019 ;
     RECT  44.208 2.245 44.232 4.019 ;
     RECT  40.2 3.733 40.872 4.117 ;
     RECT  15.9 2.151 16.212 4.261 ;
     RECT  2.4 2.821 2.808 4.355 ;
     RECT  20.736 3.829 22.2 4.499 ;
     RECT  4.56 3.925 5.412 4.501 ;
     RECT  10.272 2.341 10.812 4.501 ;
     RECT  15.9 4.261 16.92 4.501 ;
     RECT  37.5 2.151 37.812 4.501 ;
     RECT  45.6 3.539 45.912 4.501 ;
     RECT  39.456 4.117 40.872 4.643 ;
     RECT  10.272 4.501 11.256 4.691 ;
     RECT  34.8 3.875 35.352 4.789 ;
     RECT  45.6 4.501 46.008 5.077 ;
     RECT  10.5 4.691 11.256 5.125 ;
     RECT  40.2 4.643 40.872 5.173 ;
     RECT  4.56 4.501 6.312 5.267 ;
     RECT  29.04 3.299 29.712 5.365 ;
     RECT  4.56 5.267 5.412 5.459 ;
     RECT  29.04 5.365 30.312 5.459 ;
     RECT  10.5 5.125 11.736 5.603 ;
     RECT  48.3 2.151 48.612 5.605 ;
     RECT  7.8 3.685 8.232 5.747 ;
     RECT  24 4.019 25.224 5.747 ;
     RECT  44.688 5.077 46.008 5.795 ;
     RECT  29.28 5.459 30.312 6.085 ;
     RECT  31.296 3.925 32.412 6.085 ;
     RECT  29.28 6.085 32.412 6.131 ;
     RECT  18.6 2.915 18.912 6.133 ;
     RECT  47.568 5.605 48.612 6.227 ;
     RECT  21.072 4.499 22.2 6.275 ;
     RECT  34.8 4.789 35.4 6.277 ;
     RECT  21.072 6.275 21.72 6.325 ;
     RECT  26.7 4.019 27.012 6.661 ;
     RECT  28.032 6.133 28.056 6.661 ;
     RECT  40.2 5.173 40.92 6.661 ;
     RECT  5.1 5.459 5.412 6.805 ;
     RECT  6.432 5.605 6.456 6.805 ;
     RECT  7.8 5.747 8.112 6.805 ;
     RECT  18.6 6.133 19.032 6.805 ;
     RECT  20.496 6.325 21.72 6.805 ;
     RECT  29.28 6.131 31.08 6.899 ;
     RECT  18.6 6.805 21.72 6.947 ;
     RECT  18.6 6.947 19.032 7.379 ;
     RECT  34.08 6.277 35.4 7.379 ;
     RECT  10.5 5.603 11.256 7.381 ;
     RECT  13.2 2.151 13.512 7.381 ;
     RECT  5.1 6.805 6.456 7.475 ;
     RECT  29.28 6.899 30.312 7.909 ;
     RECT  32.1 6.131 32.412 7.909 ;
     RECT  20.4 6.947 21.72 8.003 ;
     RECT  44.688 5.795 45.912 8.437 ;
     RECT  10.5 7.381 13.512 8.485 ;
     RECT  3.984 7.381 4.008 8.531 ;
     RECT  7.8 6.805 8.52 8.531 ;
     RECT  9.936 8.485 13.512 8.531 ;
     RECT  22.752 7.861 22.776 8.531 ;
     RECT  25.536 6.661 25.56 8.771 ;
     RECT  34.8 7.379 35.112 8.821 ;
     RECT  44.688 8.437 46.008 8.821 ;
     RECT  26.7 6.661 28.056 8.965 ;
     RECT  5.1 7.475 5.544 9.155 ;
     RECT  29.28 7.909 32.412 9.251 ;
     RECT  25.968 8.965 28.056 9.347 ;
     RECT  14.64 7.381 14.664 9.349 ;
     RECT  15.9 4.501 16.968 9.349 ;
     RECT  29.28 9.251 30.648 9.397 ;
     RECT  36.72 4.501 37.812 9.589 ;
     RECT  14.64 9.349 16.968 9.637 ;
     RECT  9.936 8.531 11.688 9.779 ;
     RECT  14.64 9.637 17.064 9.923 ;
     RECT  28.944 9.397 30.648 10.211 ;
     RECT  42.9 2.151 43.212 10.309 ;
     RECT  20.4 8.003 21.612 10.357 ;
     RECT  44.688 8.821 46.104 10.835 ;
     RECT  29.4 10.211 30.648 10.883 ;
     RECT  36.72 9.589 37.944 10.883 ;
     RECT  20.352 10.357 21.612 10.933 ;
     RECT  15.9 9.923 17.064 10.979 ;
     RECT  25.968 9.347 27.96 11.365 ;
     RECT  29.4 10.883 30.312 11.365 ;
     RECT  34.32 8.821 35.112 11.365 ;
     RECT  25.968 11.365 30.312 11.411 ;
     RECT  36.72 10.883 37.812 11.411 ;
     RECT  7.8 8.531 8.112 11.797 ;
     RECT  15.9 10.979 16.212 11.941 ;
     RECT  18.6 7.379 18.912 11.941 ;
     RECT  44.688 10.835 46.008 11.941 ;
     RECT  10.5 9.779 11.688 11.989 ;
     RECT  13.2 8.531 13.512 11.989 ;
     RECT  28.464 11.411 30.312 11.989 ;
     RECT  34.32 11.365 35.352 12.035 ;
     RECT  7.8 11.797 9 12.181 ;
     RECT  5.1 9.155 5.412 12.229 ;
     RECT  15.792 11.941 16.212 12.229 ;
     RECT  7.8 12.181 9.384 12.517 ;
     RECT  10.5 11.989 13.512 12.517 ;
     RECT  20.352 10.933 21.912 12.517 ;
     RECT  22.944 12.373 22.968 12.517 ;
     RECT  44.688 11.941 46.728 12.563 ;
     RECT  42.9 10.309 43.32 12.565 ;
     RECT  28.464 11.989 30.792 12.755 ;
     RECT  48.3 6.227 48.612 12.757 ;
     RECT  25.968 11.411 27.144 12.803 ;
     RECT  17.184 11.365 17.208 12.899 ;
     RECT  20.352 12.517 22.968 12.899 ;
     RECT  26.7 12.803 27.144 12.899 ;
     RECT  34.32 12.035 35.112 12.899 ;
     RECT  4.896 12.229 5.412 13.091 ;
     RECT  42.9 12.565 43.416 13.091 ;
     RECT  15.648 12.229 16.212 13.093 ;
     RECT  24 5.747 24.312 13.093 ;
     RECT  15.648 13.093 17.16 13.139 ;
     RECT  24 13.093 25.08 13.235 ;
     RECT  7.8 12.517 13.512 13.283 ;
     RECT  15.792 13.139 17.16 13.331 ;
     RECT  40.2 6.661 41.4 13.573 ;
     RECT  34.8 12.899 35.112 13.621 ;
     RECT  37.2 11.411 37.812 13.715 ;
     RECT  7.8 13.283 11.688 13.811 ;
     RECT  20.352 12.899 22.824 13.909 ;
     RECT  18.48 11.941 18.912 14.005 ;
     RECT  28.608 12.755 30.264 14.099 ;
     RECT  5.1 13.091 5.412 14.101 ;
     RECT  34.8 13.621 35.352 14.147 ;
     RECT  44.688 12.563 45.912 14.197 ;
     RECT  47.328 12.757 48.612 14.197 ;
     RECT  44.688 14.197 48.612 14.291 ;
     RECT  39.888 13.573 41.4 14.293 ;
     RECT  26.7 12.899 27.012 14.677 ;
     RECT  17.616 14.005 18.912 14.723 ;
     RECT  14.64 9.923 14.664 14.773 ;
     RECT  15.792 13.331 16.212 14.773 ;
     RECT  10.224 13.811 11.688 14.821 ;
     RECT  12.672 13.283 13.512 14.821 ;
     RECT  39.744 14.293 41.4 14.867 ;
     RECT  7.8 13.811 9.24 14.915 ;
     RECT  10.224 14.821 13.656 14.963 ;
     RECT  29.4 14.099 30.264 15.059 ;
     RECT  10.224 14.963 13.512 15.155 ;
     RECT  34.8 14.147 35.208 15.205 ;
     RECT  39.744 14.867 41.304 15.251 ;
     RECT  18.48 14.723 18.912 15.349 ;
     RECT  20.208 13.909 22.824 15.349 ;
     RECT  18.48 15.349 22.824 15.491 ;
     RECT  7.8 14.915 8.112 15.733 ;
     RECT  5.1 14.101 6.312 15.925 ;
     RECT  37.5 13.715 37.812 15.925 ;
     RECT  42.9 13.091 43.212 15.925 ;
     RECT  9.216 14.915 9.24 15.973 ;
     RECT  10.224 15.155 11.976 15.973 ;
     RECT  9.216 15.973 11.976 16.019 ;
     RECT  14.64 14.773 16.212 16.019 ;
     RECT  34.8 15.205 35.448 16.019 ;
     RECT  18.48 15.491 20.232 16.117 ;
     RECT  2.4 4.355 2.712 16.165 ;
     RECT  26.448 14.677 27.012 16.261 ;
     RECT  13.008 15.155 13.512 16.403 ;
     RECT  44.688 14.291 46.392 16.405 ;
     RECT  42.768 15.925 43.212 16.453 ;
     RECT  44.4 16.405 46.392 16.453 ;
     RECT  34.8 16.019 35.352 16.501 ;
     RECT  17.568 16.117 20.232 16.595 ;
     RECT  21.3 15.491 22.824 16.595 ;
     RECT  42.768 16.453 46.392 16.835 ;
     RECT  26.448 16.261 27.768 16.837 ;
     RECT  29.4 15.059 30.12 17.077 ;
     RECT  32.1 9.251 32.412 17.077 ;
     RECT  37.5 15.925 38.088 17.077 ;
     RECT  5.1 15.925 6.648 17.123 ;
     RECT  17.568 16.595 18.912 17.123 ;
     RECT  24 13.235 24.312 17.125 ;
     RECT  25.296 17.077 25.32 17.125 ;
     RECT  6.624 17.123 6.648 17.171 ;
     RECT  29.04 17.077 32.412 17.219 ;
     RECT  37.056 17.077 38.952 17.219 ;
     RECT  24 17.125 25.32 17.363 ;
     RECT  7.68 15.733 8.112 17.365 ;
     RECT  2.4 16.165 3.48 17.411 ;
     RECT  38.928 17.219 38.952 17.413 ;
     RECT  38.928 17.413 39.192 17.459 ;
     RECT  26.352 16.837 27.768 17.603 ;
     RECT  6.912 17.365 8.112 17.605 ;
     RECT  9.216 16.019 10.812 17.605 ;
     RECT  42.9 16.835 46.392 17.699 ;
     RECT  33.984 16.501 35.352 17.747 ;
     RECT  44.4 17.699 46.392 17.843 ;
     RECT  24 17.363 25.176 17.939 ;
     RECT  20.016 16.595 20.232 17.989 ;
     RECT  18.48 17.123 18.912 18.133 ;
     RECT  18.192 18.133 18.912 18.181 ;
     RECT  48.3 14.291 48.612 18.181 ;
     RECT  21.3 16.595 22.056 18.229 ;
     RECT  19.968 17.989 20.232 18.419 ;
     RECT  39.168 17.459 39.192 18.467 ;
     RECT  37.5 17.219 37.812 18.565 ;
     RECT  2.4 17.411 2.712 18.757 ;
     RECT  26.352 17.603 27.012 18.757 ;
     RECT  33.984 17.747 35.304 18.757 ;
     RECT  36.336 17.989 36.36 18.757 ;
     RECT  33.984 18.757 36.36 18.803 ;
     RECT  44.4 17.843 45.912 18.803 ;
     RECT  29.4 17.219 32.412 18.995 ;
     RECT  37.392 18.565 37.812 18.997 ;
     RECT  40.2 15.251 41.304 19.091 ;
     RECT  29.4 18.995 30.552 19.237 ;
     RECT  6.912 17.605 10.812 19.333 ;
     RECT  45.6 18.803 45.912 19.333 ;
     RECT  6.384 19.333 10.812 19.427 ;
     RECT  24 17.939 24.792 19.427 ;
     RECT  37.392 18.997 38.424 19.427 ;
     RECT  26.352 18.757 27.48 19.523 ;
     RECT  13.2 16.403 13.512 19.525 ;
     RECT  19.968 18.419 19.992 19.811 ;
     RECT  21.3 18.229 22.2 19.909 ;
     RECT  6.384 19.427 8.52 20.003 ;
     RECT  45.6 19.333 46.2 20.003 ;
     RECT  12 18.997 12.024 20.051 ;
     RECT  2.4 18.757 2.808 20.099 ;
     RECT  33.984 18.803 35.832 20.293 ;
     RECT  21.3 19.909 22.248 20.339 ;
     RECT  33.744 20.293 35.832 20.339 ;
     RECT  40.2 19.091 40.512 20.437 ;
     RECT  41.568 19.093 41.592 20.437 ;
     RECT  44.4 18.803 44.424 20.437 ;
     RECT  13.2 19.525 13.608 20.533 ;
     RECT  14.64 16.019 14.664 20.533 ;
     RECT  3.984 18.949 4.008 20.579 ;
     RECT  13.2 20.533 14.664 20.579 ;
     RECT  17.28 18.181 18.912 20.579 ;
     RECT  29.28 19.237 30.552 20.579 ;
     RECT  29.28 20.579 30.072 20.627 ;
     RECT  13.2 20.579 14.52 20.915 ;
     RECT  40.2 20.437 41.592 21.061 ;
     RECT  45.6 20.003 45.912 21.061 ;
     RECT  9.792 19.427 10.812 21.155 ;
     RECT  24 19.427 24.6 21.155 ;
     RECT  33.744 20.339 33.768 21.155 ;
     RECT  40.2 21.061 41.736 21.155 ;
     RECT  44.208 20.437 44.424 21.299 ;
     RECT  48.3 18.181 48.744 21.443 ;
     RECT  5.1 17.123 5.412 21.541 ;
     RECT  20.208 21.109 20.232 21.587 ;
     RECT  21.3 20.339 21.768 21.637 ;
     RECT  44.4 21.299 44.424 21.683 ;
     RECT  32.1 18.995 32.412 21.973 ;
     RECT  29.4 20.627 30.072 22.069 ;
     RECT  24 21.155 24.408 22.165 ;
     RECT  7.2 20.003 8.52 22.259 ;
     RECT  21.3 21.637 22.2 22.451 ;
     RECT  42.9 17.699 43.212 22.549 ;
     RECT  14.496 20.915 14.52 22.741 ;
     RECT  15.9 16.019 16.212 22.741 ;
     RECT  26.352 19.523 27.012 22.741 ;
     RECT  40.2 21.155 40.512 22.741 ;
     RECT  48.3 21.443 48.612 22.741 ;
     RECT  47.856 22.741 48.612 23.075 ;
     RECT  48.3 23.075 48.612 23.317 ;
     RECT  32.1 21.973 32.52 23.363 ;
     RECT  41.712 21.155 41.736 23.411 ;
     RECT  45.6 21.061 46.296 23.411 ;
     RECT  14.496 22.741 16.584 23.555 ;
     RECT  26.352 22.741 27.384 23.747 ;
     RECT  34.8 20.339 35.832 24.085 ;
     RECT  24 22.165 24.936 24.227 ;
     RECT  29.4 22.069 30.168 24.229 ;
     RECT  17.904 20.579 18.912 24.469 ;
     RECT  45.6 23.411 46.056 24.469 ;
     RECT  42.768 22.549 43.212 24.515 ;
     RECT  4.992 21.541 5.412 24.563 ;
     RECT  10.08 21.155 10.812 24.659 ;
     RECT  48.3 23.317 48.744 24.659 ;
     RECT  14.496 23.555 16.212 24.661 ;
     RECT  13.2 20.915 13.512 24.901 ;
     RECT  14.496 24.661 16.392 24.901 ;
     RECT  40.08 22.741 40.512 25.043 ;
     RECT  13.2 24.901 16.392 25.139 ;
     RECT  29.4 24.229 30.312 25.139 ;
     RECT  45.6 24.469 46.536 25.235 ;
     RECT  24 24.227 24.312 25.621 ;
     RECT  29.4 25.139 29.712 25.621 ;
     RECT  32.1 23.363 32.412 25.621 ;
     RECT  21.3 22.451 21.768 25.669 ;
     RECT  42.9 24.515 43.212 25.717 ;
     RECT  7.2 22.259 8.112 25.763 ;
     RECT  21.3 25.669 21.864 25.765 ;
     RECT  23.04 25.621 24.312 25.765 ;
     RECT  26.352 23.747 27.144 25.811 ;
     RECT  13.2 25.139 14.52 26.099 ;
     RECT  31.536 25.621 32.412 26.149 ;
     RECT  21.3 25.765 24.312 26.197 ;
     RECT  20.592 26.197 24.312 26.243 ;
     RECT  37.5 19.427 38.424 26.243 ;
     RECT  31.536 26.149 33 26.245 ;
     RECT  29.28 25.621 29.712 26.291 ;
     RECT  30.768 26.245 33 26.291 ;
     RECT  32.1 26.291 33 26.293 ;
     RECT  34.8 24.085 36.456 26.293 ;
     RECT  37.5 26.243 37.812 26.293 ;
     RECT  34.8 26.293 37.812 26.339 ;
     RECT  13.2 26.099 14.088 26.531 ;
     RECT  0.144 26.293 0.168 26.579 ;
     RECT  45.6 25.235 46.488 26.725 ;
     RECT  42.144 25.717 43.212 26.771 ;
     RECT  45.264 26.725 46.488 26.771 ;
     RECT  9.312 24.901 9.336 26.773 ;
     RECT  10.5 24.659 10.812 26.773 ;
     RECT  9.312 26.773 10.812 26.819 ;
     RECT  7.8 25.763 8.112 27.109 ;
     RECT  40.2 25.043 40.512 27.301 ;
     RECT  44.208 26.197 44.232 27.347 ;
     RECT  6.96 27.109 8.112 27.587 ;
     RECT  30.768 26.291 30.792 27.587 ;
     RECT  9.648 26.819 10.812 27.875 ;
     RECT  45.264 26.771 45.912 27.875 ;
     RECT  13.2 26.531 13.512 27.877 ;
     RECT  24 26.243 24.312 27.877 ;
     RECT  26.352 25.811 27.012 27.877 ;
     RECT  32.1 26.293 33.384 27.877 ;
     RECT  34.8 26.339 35.112 27.877 ;
     RECT  36.144 26.339 37.812 27.971 ;
     RECT  29.4 26.291 29.712 27.973 ;
     RECT  29.4 27.973 29.976 28.213 ;
     RECT  29.232 28.213 29.976 28.501 ;
     RECT  25.968 27.877 27.012 28.547 ;
     RECT  28.416 28.501 29.976 28.643 ;
     RECT  45.504 27.875 45.912 28.835 ;
     RECT  17.904 24.469 19.032 28.981 ;
     RECT  20.592 26.243 22.584 28.981 ;
     RECT  23.664 27.877 24.312 29.029 ;
     RECT  13.2 27.877 14.232 29.077 ;
     RECT  17.904 28.981 22.584 29.363 ;
     RECT  28.416 28.643 29.712 29.507 ;
     RECT  7.008 27.587 8.112 29.605 ;
     RECT  28.896 29.507 29.712 29.605 ;
     RECT  18.6 29.363 22.584 29.699 ;
     RECT  32.1 27.877 35.112 29.699 ;
     RECT  3.792 28.453 3.816 29.747 ;
     RECT  13.056 29.077 14.232 30.035 ;
     RECT  18.6 29.699 19.032 30.035 ;
     RECT  10.5 27.875 10.812 30.037 ;
     RECT  15.9 25.139 16.392 30.181 ;
     RECT  36.144 27.971 36.456 30.229 ;
     RECT  37.5 27.971 37.812 30.229 ;
     RECT  15.9 30.181 16.776 30.325 ;
     RECT  36.144 30.229 37.812 30.515 ;
     RECT  26.352 28.547 27.012 30.565 ;
     RECT  7.008 29.605 8.76 30.709 ;
     RECT  36.144 30.515 36.456 30.755 ;
     RECT  34.8 29.699 35.112 30.757 ;
     RECT  40.2 27.301 40.728 30.803 ;
     RECT  28.896 29.605 30.216 30.851 ;
     RECT  0.144 29.845 0.168 31.139 ;
     RECT  15.696 30.325 16.776 31.139 ;
     RECT  37.5 30.515 37.812 31.285 ;
     RECT  40.2 30.803 40.512 31.285 ;
     RECT  39.072 28.453 39.096 31.379 ;
     RECT  44.208 29.509 44.232 31.379 ;
     RECT  15.696 31.139 16.728 31.525 ;
     RECT  6.576 30.709 8.76 31.765 ;
     RECT  28.896 30.851 29.712 31.811 ;
     RECT  18.6 30.035 18.912 31.909 ;
     RECT  29.232 31.811 29.712 31.955 ;
     RECT  6.576 31.765 8.904 32.003 ;
     RECT  25.632 30.565 27.012 32.195 ;
     RECT  18.6 31.909 19.032 32.341 ;
     RECT  11.808 31.237 11.832 32.483 ;
     RECT  18.6 32.341 19.608 32.485 ;
     RECT  13.2 30.035 14.232 32.531 ;
     RECT  15.408 31.525 16.728 32.531 ;
     RECT  40.08 31.285 40.512 32.725 ;
     RECT  40.08 32.725 40.92 32.771 ;
     RECT  40.2 32.771 40.92 32.773 ;
     RECT  42.9 26.771 43.212 32.917 ;
     RECT  48.3 24.659 48.612 32.917 ;
     RECT  18.48 32.485 19.608 33.013 ;
     RECT  20.592 29.699 22.584 33.013 ;
     RECT  23.616 29.029 24.312 33.013 ;
     RECT  45.6 28.835 45.912 33.013 ;
     RECT  31.008 31.861 31.032 33.059 ;
     RECT  34.512 30.757 35.112 33.059 ;
     RECT  37.5 31.285 37.944 33.059 ;
     RECT  15.408 32.531 16.392 33.107 ;
     RECT  18.48 33.013 22.584 33.107 ;
     RECT  42.9 32.917 43.32 33.445 ;
     RECT  29.28 31.955 29.712 33.493 ;
     RECT  23.616 33.013 25.224 33.587 ;
     RECT  42.768 33.445 43.32 33.635 ;
     RECT  34.608 33.059 35.112 33.637 ;
     RECT  36.192 30.755 36.456 33.637 ;
     RECT  15.696 33.107 16.392 33.683 ;
     RECT  32.1 29.699 33.384 33.683 ;
     RECT  42.9 33.635 43.32 33.683 ;
     RECT  26.352 32.195 27.012 33.925 ;
     RECT  40.2 32.773 41.736 33.971 ;
     RECT  45.504 33.013 45.912 34.117 ;
     RECT  40.2 33.971 40.92 34.165 ;
     RECT  45.216 34.117 45.912 34.165 ;
     RECT  29.28 33.493 30.312 34.213 ;
     RECT  47.328 32.917 48.612 34.259 ;
     RECT  29.28 34.213 30.792 34.309 ;
     RECT  32.1 33.683 32.412 34.309 ;
     RECT  29.28 34.309 32.412 34.355 ;
     RECT  5.1 24.563 5.412 34.357 ;
     RECT  13.2 32.531 13.512 34.357 ;
     RECT  34.608 33.637 36.456 34.739 ;
     RECT  9.936 30.037 10.812 34.741 ;
     RECT  44.256 34.165 45.912 34.741 ;
     RECT  44.256 34.741 46.728 34.787 ;
     RECT  5.1 34.357 5.736 34.835 ;
     RECT  6.864 32.003 8.904 34.835 ;
     RECT  39.36 34.165 40.92 34.835 ;
     RECT  23.616 33.587 24.312 34.885 ;
     RECT  15.9 33.683 16.392 34.933 ;
     RECT  18.6 33.107 22.584 34.979 ;
     RECT  29.28 34.355 29.712 35.267 ;
     RECT  9.936 34.741 10.92 35.317 ;
     RECT  26.352 33.925 27.912 35.363 ;
     RECT  31.248 34.355 32.412 35.363 ;
     RECT  45.6 34.787 46.728 35.363 ;
     RECT  34.8 34.739 36.456 35.509 ;
     RECT  37.5 33.059 37.812 35.509 ;
     RECT  26.352 35.363 27.012 35.557 ;
     RECT  34.8 35.509 37.812 35.797 ;
     RECT  39.36 34.835 40.512 35.843 ;
     RECT  7.2 34.835 8.904 35.845 ;
     RECT  9.936 35.317 11.4 35.845 ;
     RECT  7.2 35.845 11.4 35.939 ;
     RECT  18.6 34.979 19.608 35.939 ;
     RECT  12.528 34.357 13.512 35.987 ;
     RECT  15.6 34.933 16.392 36.035 ;
     RECT  3.936 34.741 3.96 36.467 ;
     RECT  23.616 34.885 24.408 36.517 ;
     RECT  25.68 35.557 27.012 36.517 ;
     RECT  7.2 35.939 10.92 36.563 ;
     RECT  18.6 35.939 18.912 36.901 ;
     RECT  31.584 35.363 32.412 36.949 ;
     RECT  42.9 33.683 43.212 36.949 ;
     RECT  44.256 34.787 44.28 36.949 ;
     RECT  31.584 36.949 32.712 36.997 ;
     RECT  39.84 35.843 40.512 37.043 ;
     RECT  18.6 36.901 19.464 37.045 ;
     RECT  7.2 36.563 8.904 37.091 ;
     RECT  23.616 36.517 27.012 37.091 ;
     RECT  47.04 36.421 47.064 37.091 ;
     RECT  28.176 36.997 28.2 37.475 ;
     RECT  5.1 34.835 5.412 37.573 ;
     RECT  0.144 37.909 0.168 38.195 ;
     RECT  2.4 20.099 2.712 38.197 ;
     RECT  7.8 37.091 8.904 38.389 ;
     RECT  9.936 36.563 10.92 38.389 ;
     RECT  42.9 36.949 44.28 38.437 ;
     RECT  42.9 38.437 44.376 38.483 ;
     RECT  17.664 37.045 19.464 38.531 ;
     RECT  18.48 38.531 19.464 38.677 ;
     RECT  20.592 34.979 22.584 38.677 ;
     RECT  29.4 35.267 29.712 38.677 ;
     RECT  45.6 35.363 45.912 38.677 ;
     RECT  23.616 37.091 25.224 38.723 ;
     RECT  31.344 36.997 32.712 38.723 ;
     RECT  34.8 35.797 37.944 38.725 ;
     RECT  39.072 38.005 39.096 38.725 ;
     RECT  40.08 37.043 40.512 38.771 ;
     RECT  24 38.723 25.224 38.819 ;
     RECT  32.1 38.723 32.712 38.819 ;
     RECT  34.8 38.725 39.096 38.819 ;
     RECT  0.192 38.965 0.216 39.251 ;
     RECT  42.9 38.483 43.212 39.253 ;
     RECT  7.8 38.389 10.92 39.395 ;
     RECT  44.256 38.483 44.376 39.445 ;
     RECT  45.6 38.677 46.2 39.445 ;
     RECT  29.28 38.677 29.712 39.539 ;
     RECT  13.2 35.987 13.512 39.637 ;
     RECT  26.352 37.091 27.012 39.637 ;
     RECT  27.984 39.301 28.008 39.637 ;
     RECT  18.48 38.677 22.584 39.685 ;
     RECT  26.352 39.637 28.008 39.827 ;
     RECT  18.48 39.685 22.68 39.877 ;
     RECT  32.1 38.819 32.412 39.877 ;
     RECT  42.048 39.253 43.212 39.877 ;
     RECT  44.256 39.445 46.2 39.877 ;
     RECT  36.432 38.819 39.096 39.923 ;
     RECT  26.592 39.827 28.008 40.067 ;
     RECT  18.24 39.877 22.728 40.163 ;
     RECT  15.9 36.035 16.392 40.261 ;
     RECT  2.4 38.197 3.672 40.357 ;
     RECT  5.1 37.573 5.64 40.405 ;
     RECT  13.2 39.637 13.704 40.405 ;
     RECT  42.048 39.877 46.2 40.499 ;
     RECT  32.1 39.877 33.048 40.595 ;
     RECT  37.5 39.923 39.096 40.595 ;
     RECT  42.048 40.499 45.912 40.595 ;
     RECT  26.592 40.067 27.96 40.691 ;
     RECT  42.048 40.595 44.28 40.691 ;
     RECT  15.9 40.261 16.488 40.787 ;
     RECT  7.8 39.395 8.904 40.835 ;
     RECT  40.2 38.771 40.512 40.981 ;
     RECT  20.88 40.163 22.728 41.027 ;
     RECT  24 38.819 24.408 41.171 ;
     RECT  20.88 41.027 22.68 41.221 ;
     RECT  26.7 40.691 27.96 41.411 ;
     RECT  36.432 39.923 36.456 41.411 ;
     RECT  18.24 40.163 19.464 41.459 ;
     RECT  13.2 40.405 13.848 41.555 ;
     RECT  24 41.171 24.312 41.605 ;
     RECT  30.816 39.301 30.84 41.605 ;
     RECT  30.816 41.605 31.128 41.651 ;
     RECT  39.792 40.981 40.512 41.651 ;
     RECT  23.904 41.605 24.312 41.747 ;
     RECT  18.48 41.459 19.464 41.939 ;
     RECT  25.68 41.701 25.704 41.987 ;
     RECT  7.8 40.835 8.712 41.989 ;
     RECT  2.4 40.357 3.96 42.133 ;
     RECT  5.1 40.405 5.688 42.133 ;
     RECT  42.048 40.691 44.184 42.133 ;
     RECT  41.808 42.133 44.184 42.179 ;
     RECT  2.4 42.133 5.688 42.181 ;
     RECT  7.44 41.989 8.712 42.227 ;
     RECT  31.104 41.651 31.128 42.469 ;
     RECT  32.1 40.595 32.412 42.469 ;
     RECT  34.8 38.819 35.208 42.565 ;
     RECT  15.9 40.787 16.392 42.709 ;
     RECT  7.44 42.227 8.112 42.851 ;
     RECT  11.952 41.557 11.976 42.853 ;
     RECT  13.2 41.555 13.704 42.853 ;
     RECT  2.4 42.181 6.12 42.899 ;
     RECT  31.104 42.469 32.412 42.947 ;
     RECT  4.8 42.899 6.12 42.995 ;
     RECT  51.696 42.757 51.72 43.091 ;
     RECT  11.952 42.853 13.704 43.093 ;
     RECT  24 41.747 24.312 43.093 ;
     RECT  18.6 41.939 19.464 43.141 ;
     RECT  15.9 42.709 17.256 43.285 ;
     RECT  18.6 43.141 19.8 43.285 ;
     RECT  48.3 34.259 48.612 43.285 ;
     RECT  15.9 43.285 19.8 43.331 ;
     RECT  41.808 42.179 41.832 43.333 ;
     RECT  42.9 42.179 44.184 43.333 ;
     RECT  24 43.093 24.552 43.379 ;
     RECT  34.8 42.565 35.256 43.667 ;
     RECT  9.936 39.395 10.92 43.765 ;
     RECT  11.952 43.093 13.944 43.765 ;
     RECT  40.2 41.651 40.512 43.813 ;
     RECT  41.808 43.333 44.184 43.813 ;
     RECT  29.4 39.539 29.712 43.861 ;
     RECT  4.8 42.995 5.688 43.955 ;
     RECT  17.616 43.331 19.8 43.955 ;
     RECT  18.6 43.955 19.8 44.053 ;
     RECT  20.784 41.221 22.68 44.053 ;
     RECT  31.104 42.947 31.128 44.149 ;
     RECT  32.1 42.947 32.412 44.149 ;
     RECT  31.104 44.149 32.412 44.195 ;
     RECT  29.232 43.861 29.712 44.435 ;
     RECT  4.992 43.955 5.688 44.483 ;
     RECT  31.296 44.195 32.412 44.531 ;
     RECT  9.936 43.765 13.944 44.579 ;
     RECT  40.2 43.813 44.184 44.579 ;
     RECT  47.424 43.285 48.612 44.579 ;
     RECT  24 43.379 24.312 44.869 ;
     RECT  40.2 44.579 41.832 44.915 ;
     RECT  2.4 42.899 3.672 44.963 ;
     RECT  18.6 44.053 22.68 44.965 ;
     RECT  23.712 44.869 24.312 44.965 ;
     RECT  25.68 44.437 25.704 44.965 ;
     RECT  26.7 41.411 27.012 44.965 ;
     RECT  37.5 40.595 38.472 44.965 ;
     RECT  9.936 44.579 13.704 45.059 ;
     RECT  25.68 44.965 27.012 45.203 ;
     RECT  36.768 44.965 38.568 45.203 ;
     RECT  42.9 44.579 44.184 45.541 ;
     RECT  45.6 40.595 45.912 45.541 ;
     RECT  7.584 42.851 8.112 45.635 ;
     RECT  9.936 45.059 11.976 45.635 ;
     RECT  2.4 44.963 2.712 46.069 ;
     RECT  32.1 44.531 32.412 46.069 ;
     RECT  4.992 44.483 5.412 46.211 ;
     RECT  13.2 45.059 13.704 46.211 ;
     RECT  18.6 44.965 24.312 46.211 ;
     RECT  36.768 45.203 37.944 46.211 ;
     RECT  20.544 46.211 24.312 46.259 ;
     RECT  26.16 45.203 27.012 46.259 ;
     RECT  13.2 46.211 13.512 46.357 ;
     RECT  9.936 45.635 11.16 46.403 ;
     RECT  20.544 46.259 22.584 46.499 ;
     RECT  18.6 46.211 18.912 46.741 ;
     RECT  2.4 46.069 3.432 46.787 ;
     RECT  15.9 43.331 16.536 46.787 ;
     RECT  23.712 46.259 24.312 46.787 ;
     RECT  31.488 46.069 33.096 46.787 ;
     RECT  42.9 45.541 45.912 46.787 ;
     RECT  34.8 43.667 35.208 46.789 ;
     RECT  42.9 46.787 44.184 46.835 ;
     RECT  9.936 46.403 10.92 47.075 ;
     RECT  18.48 46.741 18.912 47.075 ;
     RECT  12.624 46.357 13.512 47.221 ;
     RECT  24 46.787 24.312 47.317 ;
     RECT  41.808 44.915 41.832 47.317 ;
     RECT  42.9 46.835 43.212 47.317 ;
     RECT  12.624 47.221 14.232 47.603 ;
     RECT  20.784 46.499 22.584 47.699 ;
     RECT  29.4 44.435 29.712 47.701 ;
     RECT  37.5 46.211 37.944 47.747 ;
     RECT  41.808 47.317 43.212 47.891 ;
     RECT  31.488 46.787 32.412 47.939 ;
     RECT  24 47.317 24.504 48.179 ;
     RECT  41.952 47.891 43.212 48.179 ;
     RECT  9.936 47.075 10.812 48.563 ;
     RECT  12.624 47.603 13.512 48.947 ;
     RECT  21.072 47.699 22.584 49.043 ;
     RECT  7.632 45.635 8.112 49.235 ;
     RECT  29.04 47.701 29.712 49.475 ;
     RECT  34.8 46.789 35.352 49.523 ;
     RECT  2.4 46.787 2.712 49.689 ;
     RECT  5.1 46.211 5.412 49.689 ;
     RECT  7.8 49.235 8.112 49.689 ;
     RECT  10.5 48.563 10.812 49.689 ;
     RECT  13.2 48.947 13.512 49.689 ;
     RECT  18.6 47.075 18.912 49.689 ;
     RECT  21.3 49.043 22.584 49.689 ;
     RECT  24 48.179 24.312 49.689 ;
     RECT  26.7 46.259 27.012 49.689 ;
     RECT  29.4 49.475 29.712 49.689 ;
     RECT  32.1 47.939 32.412 49.689 ;
     RECT  34.8 49.523 35.112 49.689 ;
     RECT  37.5 47.747 37.812 49.689 ;
     RECT  40.2 44.915 40.512 49.689 ;
     RECT  42.9 48.179 43.212 49.689 ;
     RECT  45.6 46.787 45.912 49.689 ;
     RECT  48.3 44.579 48.612 49.689 ;
     RECT  2.4 49.689 2.52 49.703 ;
     RECT  5.1 49.689 5.22 49.703 ;
     RECT  7.8 49.689 7.92 49.703 ;
     RECT  10.5 49.689 10.62 49.703 ;
     RECT  13.2 49.689 13.32 49.703 ;
     RECT  15.9 46.787 16.392 49.703 ;
     RECT  18.6 49.689 18.72 49.703 ;
     RECT  21.3 49.689 21.42 49.703 ;
     RECT  24 49.689 24.12 49.703 ;
     RECT  26.7 49.689 26.82 49.703 ;
     RECT  29.4 49.689 29.52 49.703 ;
     RECT  32.1 49.689 32.22 49.703 ;
     RECT  34.8 49.689 34.92 49.703 ;
     RECT  37.5 49.689 37.62 49.703 ;
     RECT  40.2 49.689 40.32 49.703 ;
     RECT  42.9 49.689 43.02 49.703 ;
     RECT  45.6 49.689 45.72 49.703 ;
     RECT  48.3 49.689 48.42 49.703 ;
     RECT  16.368 49.703 16.392 51.587 ;
     RECT  22.56 49.689 22.584 51.731 ;
  END
END qfd_landh0d8g_116_EW_52x52
END LIBRARY
